VERSION 5.8 ;
BUSBITCHARS "[]" ;
DIVIDERCHAR "/" ;
UNITS
    DATABASE MICRONS 1000 ;
END UNITS

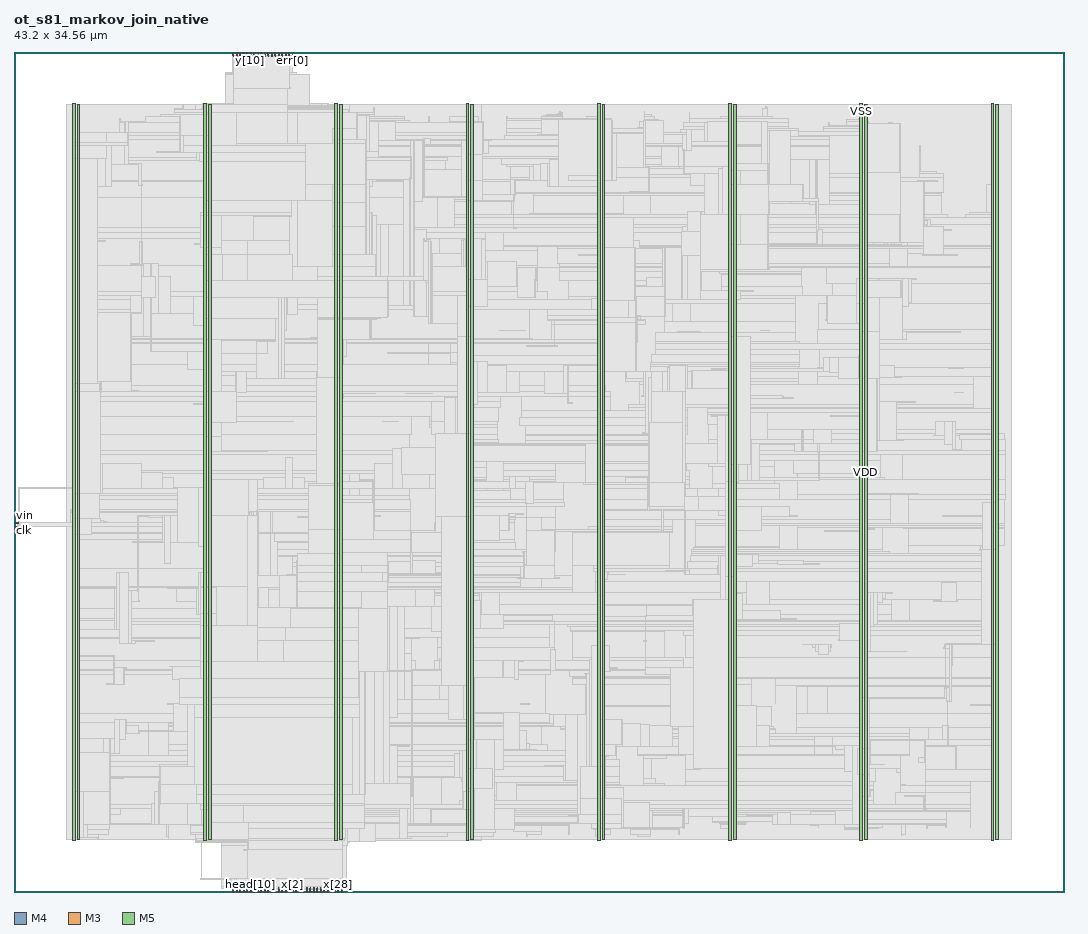
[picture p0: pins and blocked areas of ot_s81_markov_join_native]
MACRO ot_s81_markov_join_native
  FOREIGN ot_s81_markov_join_native 0 0 ;
  CLASS BLOCK ;
  SIZE 43.2 BY 34.56 ;
  PIN clk
    DIRECTION INPUT ;
    USE SIGNAL ;
    PORT
      LAYER M4 ;
        RECT  0 14.88 0.192 14.904 ;
    END
  END clk
  PIN err[0]
    DIRECTION OUTPUT ;
    USE SIGNAL ;
    PORT
      LAYER M3 ;
        RECT  11.448 34.416 11.466 34.56 ;
    END
  END err[0]
  PIN err[1]
    DIRECTION OUTPUT ;
    USE SIGNAL ;
    PORT
      LAYER M5 ;
        RECT  11.328 34.368 11.352 34.56 ;
    END
  END err[1]
  PIN head[0]
    DIRECTION INPUT ;
    USE SIGNAL ;
    PORT
      LAYER M3 ;
        RECT  9 0 9.018 0.144 ;
    END
  END head[0]
  PIN head[10]
    DIRECTION INPUT ;
    USE SIGNAL ;
    PORT
      LAYER M3 ;
        RECT  9.72 0 9.738 0.144 ;
    END
  END head[10]
  PIN head[11]
    DIRECTION INPUT ;
    USE SIGNAL ;
    PORT
      LAYER M5 ;
        RECT  9.744 0 9.768 0.192 ;
    END
  END head[11]
  PIN head[12]
    DIRECTION INPUT ;
    USE SIGNAL ;
    PORT
      LAYER M3 ;
        RECT  9.864 0 9.882 0.144 ;
    END
  END head[12]
  PIN head[13]
    DIRECTION INPUT ;
    USE SIGNAL ;
    PORT
      LAYER M5 ;
        RECT  9.888 0 9.912 0.192 ;
    END
  END head[13]
  PIN head[14]
    DIRECTION INPUT ;
    USE SIGNAL ;
    PORT
      LAYER M3 ;
        RECT  10.008 0 10.026 0.144 ;
    END
  END head[14]
  PIN head[15]
    DIRECTION INPUT ;
    USE SIGNAL ;
    PORT
      LAYER M5 ;
        RECT  10.032 0 10.056 0.192 ;
    END
  END head[15]
  PIN head[16]
    DIRECTION INPUT ;
    USE SIGNAL ;
    PORT
      LAYER M3 ;
        RECT  10.152 0 10.17 0.144 ;
    END
  END head[16]
  PIN head[17]
    DIRECTION INPUT ;
    USE SIGNAL ;
    PORT
      LAYER M5 ;
        RECT  10.176 0 10.2 0.192 ;
    END
  END head[17]
  PIN head[18]
    DIRECTION INPUT ;
    USE SIGNAL ;
    PORT
      LAYER M3 ;
        RECT  10.296 0 10.314 0.144 ;
    END
  END head[18]
  PIN head[19]
    DIRECTION INPUT ;
    USE SIGNAL ;
    PORT
      LAYER M5 ;
        RECT  10.32 0 10.344 0.192 ;
    END
  END head[19]
  PIN head[1]
    DIRECTION INPUT ;
    USE SIGNAL ;
    PORT
      LAYER M5 ;
        RECT  9.024 0 9.048 0.192 ;
    END
  END head[1]
  PIN head[20]
    DIRECTION INPUT ;
    USE SIGNAL ;
    PORT
      LAYER M3 ;
        RECT  10.44 0 10.458 0.144 ;
    END
  END head[20]
  PIN head[21]
    DIRECTION INPUT ;
    USE SIGNAL ;
    PORT
      LAYER M5 ;
        RECT  10.464 0 10.488 0.192 ;
    END
  END head[21]
  PIN head[22]
    DIRECTION INPUT ;
    USE SIGNAL ;
    PORT
      LAYER M3 ;
        RECT  10.584 0 10.602 0.144 ;
    END
  END head[22]
  PIN head[23]
    DIRECTION INPUT ;
    USE SIGNAL ;
    PORT
      LAYER M5 ;
        RECT  10.608 0 10.632 0.192 ;
    END
  END head[23]
  PIN head[24]
    DIRECTION INPUT ;
    USE SIGNAL ;
    PORT
      LAYER M3 ;
        RECT  10.728 0 10.746 0.144 ;
    END
  END head[24]
  PIN head[25]
    DIRECTION INPUT ;
    USE SIGNAL ;
    PORT
      LAYER M5 ;
        RECT  10.752 0 10.776 0.192 ;
    END
  END head[25]
  PIN head[26]
    DIRECTION INPUT ;
    USE SIGNAL ;
    PORT
      LAYER M3 ;
        RECT  10.872 0 10.89 0.144 ;
    END
  END head[26]
  PIN head[27]
    DIRECTION INPUT ;
    USE SIGNAL ;
    PORT
      LAYER M5 ;
        RECT  10.896 0 10.92 0.192 ;
    END
  END head[27]
  PIN head[28]
    DIRECTION INPUT ;
    USE SIGNAL ;
    PORT
      LAYER M3 ;
        RECT  11.016 0 11.034 0.144 ;
    END
  END head[28]
  PIN head[29]
    DIRECTION INPUT ;
    USE SIGNAL ;
    PORT
      LAYER M5 ;
        RECT  11.04 0 11.064 0.192 ;
    END
  END head[29]
  PIN head[2]
    DIRECTION INPUT ;
    USE SIGNAL ;
    PORT
      LAYER M3 ;
        RECT  9.144 0 9.162 0.144 ;
    END
  END head[2]
  PIN head[30]
    DIRECTION INPUT ;
    USE SIGNAL ;
    PORT
      LAYER M3 ;
        RECT  11.16 0 11.178 0.144 ;
    END
  END head[30]
  PIN head[31]
    DIRECTION INPUT ;
    USE SIGNAL ;
    PORT
      LAYER M5 ;
        RECT  11.184 0 11.208 0.192 ;
    END
  END head[31]
  PIN head[3]
    DIRECTION INPUT ;
    USE SIGNAL ;
    PORT
      LAYER M5 ;
        RECT  9.168 0 9.192 0.192 ;
    END
  END head[3]
  PIN head[4]
    DIRECTION INPUT ;
    USE SIGNAL ;
    PORT
      LAYER M3 ;
        RECT  9.288 0 9.306 0.144 ;
    END
  END head[4]
  PIN head[5]
    DIRECTION INPUT ;
    USE SIGNAL ;
    PORT
      LAYER M5 ;
        RECT  9.312 0 9.336 0.192 ;
    END
  END head[5]
  PIN head[6]
    DIRECTION INPUT ;
    USE SIGNAL ;
    PORT
      LAYER M3 ;
        RECT  9.432 0 9.45 0.144 ;
    END
  END head[6]
  PIN head[7]
    DIRECTION INPUT ;
    USE SIGNAL ;
    PORT
      LAYER M5 ;
        RECT  9.456 0 9.48 0.192 ;
    END
  END head[7]
  PIN head[8]
    DIRECTION INPUT ;
    USE SIGNAL ;
    PORT
      LAYER M3 ;
        RECT  9.576 0 9.594 0.144 ;
    END
  END head[8]
  PIN head[9]
    DIRECTION INPUT ;
    USE SIGNAL ;
    PORT
      LAYER M5 ;
        RECT  9.6 0 9.624 0.192 ;
    END
  END head[9]
  PIN rst_n
    DIRECTION INPUT ;
    USE SIGNAL ;
    PORT
      LAYER M4 ;
        RECT  0 15.024 0.192 15.048 ;
    END
  END rst_n
  PIN vin
    DIRECTION INPUT ;
    USE SIGNAL ;
    PORT
      LAYER M4 ;
        RECT  0 15.168 0.192 15.192 ;
    END
  END vin
  PIN vout
    DIRECTION OUTPUT ;
    USE SIGNAL ;
    PORT
      LAYER M3 ;
        RECT  11.304 34.416 11.322 34.56 ;
    END
  END vout
  PIN x[0]
    DIRECTION INPUT ;
    USE SIGNAL ;
    PORT
      LAYER M3 ;
        RECT  11.304 0 11.322 0.144 ;
    END
  END x[0]
  PIN x[10]
    DIRECTION INPUT ;
    USE SIGNAL ;
    PORT
      LAYER M3 ;
        RECT  12.024 0 12.042 0.144 ;
    END
  END x[10]
  PIN x[11]
    DIRECTION INPUT ;
    USE SIGNAL ;
    PORT
      LAYER M5 ;
        RECT  12.048 0 12.072 0.192 ;
    END
  END x[11]
  PIN x[12]
    DIRECTION INPUT ;
    USE SIGNAL ;
    PORT
      LAYER M3 ;
        RECT  12.168 0 12.186 0.144 ;
    END
  END x[12]
  PIN x[13]
    DIRECTION INPUT ;
    USE SIGNAL ;
    PORT
      LAYER M5 ;
        RECT  12.192 0 12.216 0.192 ;
    END
  END x[13]
  PIN x[14]
    DIRECTION INPUT ;
    USE SIGNAL ;
    PORT
      LAYER M3 ;
        RECT  12.312 0 12.33 0.144 ;
    END
  END x[14]
  PIN x[15]
    DIRECTION INPUT ;
    USE SIGNAL ;
    PORT
      LAYER M5 ;
        RECT  12.336 0 12.36 0.192 ;
    END
  END x[15]
  PIN x[16]
    DIRECTION INPUT ;
    USE SIGNAL ;
    PORT
      LAYER M3 ;
        RECT  12.456 0 12.474 0.144 ;
    END
  END x[16]
  PIN x[17]
    DIRECTION INPUT ;
    USE SIGNAL ;
    PORT
      LAYER M5 ;
        RECT  12.48 0 12.504 0.192 ;
    END
  END x[17]
  PIN x[18]
    DIRECTION INPUT ;
    USE SIGNAL ;
    PORT
      LAYER M3 ;
        RECT  12.6 0 12.618 0.144 ;
    END
  END x[18]
  PIN x[19]
    DIRECTION INPUT ;
    USE SIGNAL ;
    PORT
      LAYER M5 ;
        RECT  12.624 0 12.648 0.192 ;
    END
  END x[19]
  PIN x[1]
    DIRECTION INPUT ;
    USE SIGNAL ;
    PORT
      LAYER M5 ;
        RECT  11.328 0 11.352 0.192 ;
    END
  END x[1]
  PIN x[20]
    DIRECTION INPUT ;
    USE SIGNAL ;
    PORT
      LAYER M3 ;
        RECT  12.744 0 12.762 0.144 ;
    END
  END x[20]
  PIN x[21]
    DIRECTION INPUT ;
    USE SIGNAL ;
    PORT
      LAYER M5 ;
        RECT  12.768 0 12.792 0.192 ;
    END
  END x[21]
  PIN x[22]
    DIRECTION INPUT ;
    USE SIGNAL ;
    PORT
      LAYER M3 ;
        RECT  12.888 0 12.906 0.144 ;
    END
  END x[22]
  PIN x[23]
    DIRECTION INPUT ;
    USE SIGNAL ;
    PORT
      LAYER M5 ;
        RECT  12.912 0 12.936 0.192 ;
    END
  END x[23]
  PIN x[24]
    DIRECTION INPUT ;
    USE SIGNAL ;
    PORT
      LAYER M3 ;
        RECT  13.032 0 13.05 0.144 ;
    END
  END x[24]
  PIN x[25]
    DIRECTION INPUT ;
    USE SIGNAL ;
    PORT
      LAYER M5 ;
        RECT  13.056 0 13.08 0.192 ;
    END
  END x[25]
  PIN x[26]
    DIRECTION INPUT ;
    USE SIGNAL ;
    PORT
      LAYER M3 ;
        RECT  13.176 0 13.194 0.144 ;
    END
  END x[26]
  PIN x[27]
    DIRECTION INPUT ;
    USE SIGNAL ;
    PORT
      LAYER M5 ;
        RECT  13.2 0 13.224 0.192 ;
    END
  END x[27]
  PIN x[28]
    DIRECTION INPUT ;
    USE SIGNAL ;
    PORT
      LAYER M3 ;
        RECT  13.32 0 13.338 0.144 ;
    END
  END x[28]
  PIN x[29]
    DIRECTION INPUT ;
    USE SIGNAL ;
    PORT
      LAYER M5 ;
        RECT  13.344 0 13.368 0.192 ;
    END
  END x[29]
  PIN x[2]
    DIRECTION INPUT ;
    USE SIGNAL ;
    PORT
      LAYER M3 ;
        RECT  11.448 0 11.466 0.144 ;
    END
  END x[2]
  PIN x[30]
    DIRECTION INPUT ;
    USE SIGNAL ;
    PORT
      LAYER M3 ;
        RECT  13.464 0 13.482 0.144 ;
    END
  END x[30]
  PIN x[31]
    DIRECTION INPUT ;
    USE SIGNAL ;
    PORT
      LAYER M5 ;
        RECT  13.488 0 13.512 0.192 ;
    END
  END x[31]
  PIN x[3]
    DIRECTION INPUT ;
    USE SIGNAL ;
    PORT
      LAYER M5 ;
        RECT  11.472 0 11.496 0.192 ;
    END
  END x[3]
  PIN x[4]
    DIRECTION INPUT ;
    USE SIGNAL ;
    PORT
      LAYER M3 ;
        RECT  11.592 0 11.61 0.144 ;
    END
  END x[4]
  PIN x[5]
    DIRECTION INPUT ;
    USE SIGNAL ;
    PORT
      LAYER M5 ;
        RECT  11.616 0 11.64 0.192 ;
    END
  END x[5]
  PIN x[6]
    DIRECTION INPUT ;
    USE SIGNAL ;
    PORT
      LAYER M3 ;
        RECT  11.736 0 11.754 0.144 ;
    END
  END x[6]
  PIN x[7]
    DIRECTION INPUT ;
    USE SIGNAL ;
    PORT
      LAYER M5 ;
        RECT  11.76 0 11.784 0.192 ;
    END
  END x[7]
  PIN x[8]
    DIRECTION INPUT ;
    USE SIGNAL ;
    PORT
      LAYER M3 ;
        RECT  11.88 0 11.898 0.144 ;
    END
  END x[8]
  PIN x[9]
    DIRECTION INPUT ;
    USE SIGNAL ;
    PORT
      LAYER M5 ;
        RECT  11.904 0 11.928 0.192 ;
    END
  END x[9]
  PIN y[0]
    DIRECTION OUTPUT ;
    USE SIGNAL ;
    PORT
      LAYER M3 ;
        RECT  9 34.416 9.018 34.56 ;
    END
  END y[0]
  PIN y[10]
    DIRECTION OUTPUT ;
    USE SIGNAL ;
    PORT
      LAYER M3 ;
        RECT  9.72 34.416 9.738 34.56 ;
    END
  END y[10]
  PIN y[11]
    DIRECTION OUTPUT ;
    USE SIGNAL ;
    PORT
      LAYER M5 ;
        RECT  9.744 34.368 9.768 34.56 ;
    END
  END y[11]
  PIN y[12]
    DIRECTION OUTPUT ;
    USE SIGNAL ;
    PORT
      LAYER M3 ;
        RECT  9.864 34.416 9.882 34.56 ;
    END
  END y[12]
  PIN y[13]
    DIRECTION OUTPUT ;
    USE SIGNAL ;
    PORT
      LAYER M5 ;
        RECT  9.888 34.368 9.912 34.56 ;
    END
  END y[13]
  PIN y[14]
    DIRECTION OUTPUT ;
    USE SIGNAL ;
    PORT
      LAYER M3 ;
        RECT  10.008 34.416 10.026 34.56 ;
    END
  END y[14]
  PIN y[15]
    DIRECTION OUTPUT ;
    USE SIGNAL ;
    PORT
      LAYER M5 ;
        RECT  10.032 34.368 10.056 34.56 ;
    END
  END y[15]
  PIN y[16]
    DIRECTION OUTPUT ;
    USE SIGNAL ;
    PORT
      LAYER M3 ;
        RECT  10.152 34.416 10.17 34.56 ;
    END
  END y[16]
  PIN y[17]
    DIRECTION OUTPUT ;
    USE SIGNAL ;
    PORT
      LAYER M5 ;
        RECT  10.176 34.368 10.2 34.56 ;
    END
  END y[17]
  PIN y[18]
    DIRECTION OUTPUT ;
    USE SIGNAL ;
    PORT
      LAYER M3 ;
        RECT  10.296 34.416 10.314 34.56 ;
    END
  END y[18]
  PIN y[19]
    DIRECTION OUTPUT ;
    USE SIGNAL ;
    PORT
      LAYER M5 ;
        RECT  10.32 34.368 10.344 34.56 ;
    END
  END y[19]
  PIN y[1]
    DIRECTION OUTPUT ;
    USE SIGNAL ;
    PORT
      LAYER M5 ;
        RECT  9.024 34.368 9.048 34.56 ;
    END
  END y[1]
  PIN y[20]
    DIRECTION OUTPUT ;
    USE SIGNAL ;
    PORT
      LAYER M3 ;
        RECT  10.44 34.416 10.458 34.56 ;
    END
  END y[20]
  PIN y[21]
    DIRECTION OUTPUT ;
    USE SIGNAL ;
    PORT
      LAYER M5 ;
        RECT  10.464 34.368 10.488 34.56 ;
    END
  END y[21]
  PIN y[22]
    DIRECTION OUTPUT ;
    USE SIGNAL ;
    PORT
      LAYER M3 ;
        RECT  10.584 34.416 10.602 34.56 ;
    END
  END y[22]
  PIN y[23]
    DIRECTION OUTPUT ;
    USE SIGNAL ;
    PORT
      LAYER M5 ;
        RECT  10.608 34.368 10.632 34.56 ;
    END
  END y[23]
  PIN y[24]
    DIRECTION OUTPUT ;
    USE SIGNAL ;
    PORT
      LAYER M3 ;
        RECT  10.728 34.416 10.746 34.56 ;
    END
  END y[24]
  PIN y[25]
    DIRECTION OUTPUT ;
    USE SIGNAL ;
    PORT
      LAYER M5 ;
        RECT  10.752 34.368 10.776 34.56 ;
    END
  END y[25]
  PIN y[26]
    DIRECTION OUTPUT ;
    USE SIGNAL ;
    PORT
      LAYER M3 ;
        RECT  10.872 34.416 10.89 34.56 ;
    END
  END y[26]
  PIN y[27]
    DIRECTION OUTPUT ;
    USE SIGNAL ;
    PORT
      LAYER M5 ;
        RECT  10.896 34.368 10.92 34.56 ;
    END
  END y[27]
  PIN y[28]
    DIRECTION OUTPUT ;
    USE SIGNAL ;
    PORT
      LAYER M3 ;
        RECT  11.016 34.416 11.034 34.56 ;
    END
  END y[28]
  PIN y[29]
    DIRECTION OUTPUT ;
    USE SIGNAL ;
    PORT
      LAYER M5 ;
        RECT  11.04 34.368 11.064 34.56 ;
    END
  END y[29]
  PIN y[2]
    DIRECTION OUTPUT ;
    USE SIGNAL ;
    PORT
      LAYER M3 ;
        RECT  9.144 34.416 9.162 34.56 ;
    END
  END y[2]
  PIN y[30]
    DIRECTION OUTPUT ;
    USE SIGNAL ;
    PORT
      LAYER M3 ;
        RECT  11.16 34.416 11.178 34.56 ;
    END
  END y[30]
  PIN y[31]
    DIRECTION OUTPUT ;
    USE SIGNAL ;
    PORT
      LAYER M5 ;
        RECT  11.184 34.368 11.208 34.56 ;
    END
  END y[31]
  PIN y[3]
    DIRECTION OUTPUT ;
    USE SIGNAL ;
    PORT
      LAYER M5 ;
        RECT  9.168 34.368 9.192 34.56 ;
    END
  END y[3]
  PIN y[4]
    DIRECTION OUTPUT ;
    USE SIGNAL ;
    PORT
      LAYER M3 ;
        RECT  9.288 34.416 9.306 34.56 ;
    END
  END y[4]
  PIN y[5]
    DIRECTION OUTPUT ;
    USE SIGNAL ;
    PORT
      LAYER M5 ;
        RECT  9.312 34.368 9.336 34.56 ;
    END
  END y[5]
  PIN y[6]
    DIRECTION OUTPUT ;
    USE SIGNAL ;
    PORT
      LAYER M3 ;
        RECT  9.432 34.416 9.45 34.56 ;
    END
  END y[6]
  PIN y[7]
    DIRECTION OUTPUT ;
    USE SIGNAL ;
    PORT
      LAYER M5 ;
        RECT  9.456 34.368 9.48 34.56 ;
    END
  END y[7]
  PIN y[8]
    DIRECTION OUTPUT ;
    USE SIGNAL ;
    PORT
      LAYER M3 ;
        RECT  9.576 34.416 9.594 34.56 ;
    END
  END y[8]
  PIN y[9]
    DIRECTION OUTPUT ;
    USE SIGNAL ;
    PORT
      LAYER M5 ;
        RECT  9.6 34.368 9.624 34.56 ;
    END
  END y[9]
  PIN VDD
    DIRECTION INOUT ;
    USE POWER ;
    PORT
      LAYER M5 ;
        RECT  40.392 2.151 40.512 32.409 ;
        RECT  34.992 2.151 35.112 32.409 ;
        RECT  29.592 2.151 29.712 32.409 ;
        RECT  24.192 2.151 24.312 32.409 ;
        RECT  18.792 2.151 18.912 32.409 ;
        RECT  13.392 2.151 13.512 32.409 ;
        RECT  7.992 2.151 8.112 32.409 ;
        RECT  2.592 2.151 2.712 32.409 ;
    END
  END VDD
  PIN VSS
    DIRECTION INOUT ;
    USE GROUND ;
    PORT
      LAYER M5 ;
        RECT  40.2 2.137 40.32 32.423 ;
        RECT  34.8 2.137 34.92 32.423 ;
        RECT  29.4 2.137 29.52 32.423 ;
        RECT  24 2.137 24.12 32.423 ;
        RECT  18.6 2.137 18.72 32.423 ;
        RECT  13.2 2.137 13.32 32.423 ;
        RECT  7.8 2.137 7.92 32.423 ;
        RECT  2.4 2.137 2.52 32.423 ;
    END
  END VSS
  # OT_OBS_CLOSED layer=M5 d_um=1.536 added=83
  OBS
    LAYER RVTN ;
     RECT  2.16 2.16 41.04 2.295 ;
     RECT  2.16 2.565 41.04 2.835 ;
     RECT  2.16 3.105 41.04 3.375 ;
     RECT  2.16 3.645 41.04 3.915 ;
     RECT  2.16 4.185 41.04 4.455 ;
     RECT  2.16 4.725 41.04 4.995 ;
     RECT  2.16 5.265 41.04 5.535 ;
     RECT  2.16 5.805 41.04 6.075 ;
     RECT  2.16 6.345 41.04 6.615 ;
     RECT  2.16 6.885 41.04 7.155 ;
     RECT  2.16 7.425 41.04 7.695 ;
     RECT  2.16 7.965 41.04 8.235 ;
     RECT  2.16 8.505 41.04 8.775 ;
     RECT  2.16 9.045 41.04 9.315 ;
     RECT  2.16 9.585 41.04 9.855 ;
     RECT  2.16 10.125 41.04 10.395 ;
     RECT  2.16 10.665 41.04 10.935 ;
     RECT  2.16 11.205 41.04 11.475 ;
     RECT  2.16 11.745 41.04 12.015 ;
     RECT  2.16 12.285 41.04 12.555 ;
     RECT  2.16 12.825 41.04 13.095 ;
     RECT  2.16 13.365 41.04 13.635 ;
     RECT  2.16 13.905 41.04 14.175 ;
     RECT  2.16 14.445 41.04 14.715 ;
     RECT  2.16 14.985 41.04 15.255 ;
     RECT  2.16 15.525 41.04 15.795 ;
     RECT  2.16 16.065 41.04 16.335 ;
     RECT  2.16 16.605 41.04 16.875 ;
     RECT  2.16 17.145 41.04 17.415 ;
     RECT  2.16 17.685 41.04 17.955 ;
     RECT  2.16 18.225 41.04 18.495 ;
     RECT  2.16 18.765 41.04 19.035 ;
     RECT  2.16 19.305 41.04 19.575 ;
     RECT  2.16 19.845 41.04 20.115 ;
     RECT  2.16 20.385 41.04 20.655 ;
     RECT  2.16 20.925 41.04 21.195 ;
     RECT  2.16 21.465 41.04 21.735 ;
     RECT  2.16 22.005 41.04 22.275 ;
     RECT  2.16 22.545 41.04 22.815 ;
     RECT  2.16 23.085 41.04 23.355 ;
     RECT  2.16 23.625 41.04 23.895 ;
     RECT  2.16 24.165 41.04 24.435 ;
     RECT  2.16 24.705 41.04 24.975 ;
     RECT  2.16 25.245 41.04 25.515 ;
     RECT  2.16 25.785 41.04 26.055 ;
     RECT  2.16 26.325 41.04 26.595 ;
     RECT  2.16 26.865 41.04 27.135 ;
     RECT  2.16 27.405 41.04 27.675 ;
     RECT  2.16 27.945 41.04 28.215 ;
     RECT  2.16 28.485 41.04 28.755 ;
     RECT  2.16 29.025 41.04 29.295 ;
     RECT  2.16 29.565 41.04 29.835 ;
     RECT  2.16 30.105 41.04 30.375 ;
     RECT  2.16 30.645 41.04 30.915 ;
     RECT  2.16 31.185 41.04 31.455 ;
     RECT  2.16 31.725 41.04 31.995 ;
     RECT  2.16 32.265 41.04 32.4 ;
    LAYER RVTP ;
     RECT  2.16 2.295 41.04 2.565 ;
     RECT  2.16 2.835 41.04 3.105 ;
     RECT  2.16 3.375 41.04 3.645 ;
     RECT  2.16 3.915 41.04 4.185 ;
     RECT  2.16 4.455 41.04 4.725 ;
     RECT  2.16 4.995 41.04 5.265 ;
     RECT  2.16 5.535 41.04 5.805 ;
     RECT  2.16 6.075 41.04 6.345 ;
     RECT  2.16 6.615 41.04 6.885 ;
     RECT  2.16 7.155 41.04 7.425 ;
     RECT  2.16 7.695 41.04 7.965 ;
     RECT  2.16 8.235 41.04 8.505 ;
     RECT  2.16 8.775 41.04 9.045 ;
     RECT  2.16 9.315 41.04 9.585 ;
     RECT  2.16 9.855 41.04 10.125 ;
     RECT  2.16 10.395 41.04 10.665 ;
     RECT  2.16 10.935 41.04 11.205 ;
     RECT  2.16 11.475 41.04 11.745 ;
     RECT  2.16 12.015 41.04 12.285 ;
     RECT  2.16 12.555 41.04 12.825 ;
     RECT  2.16 13.095 41.04 13.365 ;
     RECT  2.16 13.635 41.04 13.905 ;
     RECT  2.16 14.175 41.04 14.445 ;
     RECT  2.16 14.715 41.04 14.985 ;
     RECT  2.16 15.255 41.04 15.525 ;
     RECT  2.16 15.795 41.04 16.065 ;
     RECT  2.16 16.335 41.04 16.605 ;
     RECT  2.16 16.875 41.04 17.145 ;
     RECT  2.16 17.415 41.04 17.685 ;
     RECT  2.16 17.955 41.04 18.225 ;
     RECT  2.16 18.495 41.04 18.765 ;
     RECT  2.16 19.035 41.04 19.305 ;
     RECT  2.16 19.575 41.04 19.845 ;
     RECT  2.16 20.115 41.04 20.385 ;
     RECT  2.16 20.655 41.04 20.925 ;
     RECT  2.16 21.195 41.04 21.465 ;
     RECT  2.16 21.735 41.04 22.005 ;
     RECT  2.16 22.275 41.04 22.545 ;
     RECT  2.16 22.815 41.04 23.085 ;
     RECT  2.16 23.355 41.04 23.625 ;
     RECT  2.16 23.895 41.04 24.165 ;
     RECT  2.16 24.435 41.04 24.705 ;
     RECT  2.16 24.975 41.04 25.245 ;
     RECT  2.16 25.515 41.04 25.785 ;
     RECT  2.16 26.055 41.04 26.325 ;
     RECT  2.16 26.595 41.04 26.865 ;
     RECT  2.16 27.135 41.04 27.405 ;
     RECT  2.16 27.675 41.04 27.945 ;
     RECT  2.16 28.215 41.04 28.485 ;
     RECT  2.16 28.755 41.04 29.025 ;
     RECT  2.16 29.295 41.04 29.565 ;
     RECT  2.16 29.835 41.04 30.105 ;
     RECT  2.16 30.375 41.04 30.645 ;
     RECT  2.16 30.915 41.04 31.185 ;
     RECT  2.16 31.455 41.04 31.725 ;
     RECT  2.16 31.995 41.04 32.265 ;
    LAYER M1 ;
     RECT  2.16 2.151 41.04 32.409 ;
    LAYER M2 ;
     RECT  2.16 2.151 7.483 32.409 ;
     RECT  7.483 2.034 7.771 32.409 ;
     RECT  7.771 2.034 8.699 32.454 ;
     RECT  8.699 2.151 9.023 32.454 ;
     RECT  9.023 2.151 9.679 32.409 ;
     RECT  9.679 2.106 9.787 32.409 ;
     RECT  9.787 2.106 9.859 32.994 ;
     RECT  9.859 2.106 10.067 33.759 ;
     RECT  8.527 0.144 10.319 0.162 ;
     RECT  10.067 2.106 10.571 33.066 ;
     RECT  10.571 2.106 10.859 32.409 ;
     RECT  11.155 33.696 11.299 33.714 ;
     RECT  10.859 2.151 11.587 32.409 ;
     RECT  11.299 33.624 11.615 33.714 ;
     RECT  11.587 2.151 11.903 32.526 ;
     RECT  11.615 33.624 12.155 33.642 ;
     RECT  11.903 2.151 12.667 32.454 ;
     RECT  12.667 1.728 12.911 32.454 ;
     RECT  12.911 2.034 12.947 32.454 ;
     RECT  12.415 0.144 13.459 0.162 ;
     RECT  13.459 0.144 13.631 0.234 ;
     RECT  13.631 0.216 13.667 0.234 ;
     RECT  12.947 2.034 13.811 32.409 ;
     RECT  13.811 2.106 19.247 32.409 ;
     RECT  19.247 2.151 41.04 32.409 ;
    LAYER M3 ;
     RECT  9 0.108 13.482 0.139 ;
     RECT  8.532 0.139 13.626 0.211 ;
     RECT  8.532 0.211 13.662 1.915 ;
     RECT  7.704 0.523 7.722 2.029 ;
     RECT  8.532 1.915 13.698 2.029 ;
     RECT  7.488 2.029 7.722 2.065 ;
     RECT  8.532 2.029 13.806 2.065 ;
     RECT  7.488 2.065 13.806 2.107 ;
     RECT  14.832 2.059 14.85 2.107 ;
     RECT  19.224 2.101 19.242 2.143 ;
     RECT  7.488 2.107 14.85 2.191 ;
     RECT  2.415 2.143 2.505 2.251 ;
     RECT  3.456 2.191 3.474 2.251 ;
     RECT  6.336 2.191 6.354 2.263 ;
     RECT  16.164 2.191 16.362 2.263 ;
     RECT  16.164 2.263 17.586 2.299 ;
     RECT  18.615 2.143 19.242 2.299 ;
     RECT  24.015 2.143 24.105 2.299 ;
     RECT  26.172 2.263 26.19 2.299 ;
     RECT  2.415 2.251 3.474 2.371 ;
     RECT  7.452 2.191 14.85 2.371 ;
     RECT  21.096 2.263 21.114 2.371 ;
     RECT  23.94 2.299 24.105 2.371 ;
     RECT  25.668 2.299 26.19 2.371 ;
     RECT  36.504 2.335 36.522 2.371 ;
     RECT  29.415 2.143 29.505 2.413 ;
     RECT  34.815 2.143 34.905 2.413 ;
     RECT  40.215 2.143 40.305 2.413 ;
     RECT  7.272 2.371 15.426 2.461 ;
     RECT  16.164 2.299 17.838 2.461 ;
     RECT  18.615 2.299 19.746 2.461 ;
     RECT  21.096 2.371 21.69 2.497 ;
     RECT  2.415 2.371 3.87 2.569 ;
     RECT  23.94 2.371 24.534 2.569 ;
     RECT  25.344 2.371 26.19 2.569 ;
     RECT  27.36 2.371 27.378 2.569 ;
     RECT  34.815 2.413 35.097 2.569 ;
     RECT  23.832 2.569 24.534 2.605 ;
     RECT  25.344 2.569 27.378 2.605 ;
     RECT  29.415 2.413 29.697 2.605 ;
     RECT  34.164 2.569 35.097 2.605 ;
     RECT  34.164 2.605 35.586 2.641 ;
     RECT  7.272 2.461 19.818 2.731 ;
     RECT  20.556 2.497 21.69 2.731 ;
     RECT  22.824 2.371 22.842 2.731 ;
     RECT  33.084 2.641 33.102 2.731 ;
     RECT  37.548 2.605 37.566 2.731 ;
     RECT  38.34 2.641 38.358 2.731 ;
     RECT  6.264 2.263 6.354 2.767 ;
     RECT  7.272 2.731 22.842 2.767 ;
     RECT  29.052 2.605 29.697 2.767 ;
     RECT  34.164 2.641 35.73 2.767 ;
     RECT  36.504 2.371 36.666 2.767 ;
     RECT  37.548 2.731 38.358 2.767 ;
     RECT  31.464 2.767 31.482 2.779 ;
     RECT  5.796 2.767 22.842 2.803 ;
     RECT  23.76 2.605 27.378 2.803 ;
     RECT  29.052 2.767 30.114 2.803 ;
     RECT  33.876 2.767 35.73 2.803 ;
     RECT  36.504 2.767 38.358 2.803 ;
     RECT  5.796 2.803 27.738 2.839 ;
     RECT  29.016 2.803 30.114 2.875 ;
     RECT  28.728 2.875 30.186 2.911 ;
     RECT  31.212 2.779 31.482 2.911 ;
     RECT  32.76 2.731 33.102 3.001 ;
     RECT  33.876 2.803 38.358 3.001 ;
     RECT  5.652 2.839 27.738 3.109 ;
     RECT  28.728 2.911 31.77 3.109 ;
     RECT  2.415 2.569 3.942 3.181 ;
     RECT  5.652 3.109 31.77 3.181 ;
     RECT  5.652 3.181 31.842 3.259 ;
     RECT  32.76 3.001 38.358 3.307 ;
     RECT  39.348 2.641 39.366 3.307 ;
     RECT  5.652 3.259 31.95 3.343 ;
     RECT  32.76 3.307 39.366 3.343 ;
     RECT  2.415 3.181 4.374 3.415 ;
     RECT  5.652 3.343 39.366 3.415 ;
     RECT  2.415 3.415 39.366 3.605 ;
     RECT  18.324 3.605 35.37 3.749 ;
     RECT  18.504 3.749 19.854 3.983 ;
     RECT  36.288 3.605 39.366 4.109 ;
     RECT  20.664 3.749 35.37 4.379 ;
     RECT  36.468 4.109 39.366 4.379 ;
     RECT  20.664 4.379 24.966 4.415 ;
     RECT  36.468 4.379 36.666 4.415 ;
     RECT  25.884 4.379 26.766 4.451 ;
     RECT  19.692 3.983 19.854 4.495 ;
     RECT  20.664 4.415 24.93 4.495 ;
     RECT  18.504 3.983 18.954 4.531 ;
     RECT  27.648 4.379 35.37 4.531 ;
     RECT  37.512 4.379 39.366 4.531 ;
     RECT  40.215 2.413 40.497 4.531 ;
     RECT  25.884 4.451 26.406 4.685 ;
     RECT  2.415 3.605 17.586 4.699 ;
     RECT  18.432 4.531 18.954 4.699 ;
     RECT  2.415 4.699 18.954 4.765 ;
     RECT  19.692 4.495 24.93 4.765 ;
     RECT  36.468 4.415 36.486 4.927 ;
     RECT  27.648 4.531 35.442 5.071 ;
     RECT  36.324 4.927 36.486 5.071 ;
     RECT  2.415 4.765 24.93 5.165 ;
     RECT  37.512 4.531 40.497 5.341 ;
     RECT  2.415 5.165 22.77 5.369 ;
     RECT  23.508 5.165 24.93 5.459 ;
     RECT  25.884 4.685 26.226 5.503 ;
     RECT  37.224 5.341 40.497 5.531 ;
     RECT  2.415 5.369 22.734 5.603 ;
     RECT  25.884 5.503 26.838 5.611 ;
     RECT  27.648 5.071 36.486 5.611 ;
     RECT  25.668 5.611 36.846 5.639 ;
     RECT  6.372 5.603 22.734 5.837 ;
     RECT  6.372 5.837 21.942 6.071 ;
     RECT  23.508 5.459 24.786 6.277 ;
     RECT  25.668 5.639 32.922 6.277 ;
     RECT  37.656 5.531 40.497 6.277 ;
     RECT  23.508 6.277 32.922 6.385 ;
     RECT  33.696 5.639 36.846 6.385 ;
     RECT  23.508 6.385 36.846 6.539 ;
     RECT  22.716 5.837 22.734 6.691 ;
     RECT  23.508 6.539 31.338 6.691 ;
     RECT  22.5 6.691 31.338 6.719 ;
     RECT  32.184 6.539 36.846 6.781 ;
     RECT  37.62 6.277 40.497 6.781 ;
     RECT  22.5 6.719 31.266 6.809 ;
     RECT  6.372 6.071 21.69 6.811 ;
     RECT  22.5 6.809 22.734 6.811 ;
     RECT  6.372 6.811 22.734 6.845 ;
     RECT  6.372 6.845 22.23 6.953 ;
     RECT  2.415 5.603 5.526 6.961 ;
     RECT  6.372 6.953 22.05 6.961 ;
     RECT  2.415 6.961 22.05 7.325 ;
     RECT  32.184 6.781 40.497 7.349 ;
     RECT  23.508 6.809 31.158 7.619 ;
     RECT  23.508 7.619 30.546 7.661 ;
     RECT  32.184 7.349 32.634 8.473 ;
     RECT  33.48 7.349 40.497 8.473 ;
     RECT  31.32 7.771 31.338 8.509 ;
     RECT  32.184 8.473 40.497 8.509 ;
     RECT  23.508 7.661 30.33 8.545 ;
     RECT  22.968 8.545 30.33 8.779 ;
     RECT  31.32 8.509 40.497 8.779 ;
     RECT  22.968 8.779 40.497 8.807 ;
     RECT  22.968 8.807 27.558 8.851 ;
     RECT  2.415 7.325 21.87 8.941 ;
     RECT  2.415 8.941 22.086 9.115 ;
     RECT  22.86 8.851 27.558 9.115 ;
     RECT  2.415 9.115 27.558 9.149 ;
     RECT  2.415 9.149 16.506 9.509 ;
     RECT  17.28 9.149 27.558 9.509 ;
     RECT  17.28 9.509 22.23 9.545 ;
     RECT  22.968 9.509 27.558 9.653 ;
     RECT  28.296 8.807 40.497 9.661 ;
     RECT  17.424 9.545 22.23 10.049 ;
     RECT  2.415 9.509 16.362 10.435 ;
     RECT  2.415 10.435 16.686 10.471 ;
     RECT  17.424 10.049 22.05 10.471 ;
     RECT  27.612 9.661 40.497 10.561 ;
     RECT  22.968 9.653 26.766 10.705 ;
     RECT  22.896 10.705 26.766 10.741 ;
     RECT  27.54 10.561 40.497 10.741 ;
     RECT  22.896 10.741 40.497 10.903 ;
     RECT  2.415 10.471 22.05 11.011 ;
     RECT  22.788 10.903 40.497 11.011 ;
     RECT  2.415 11.011 40.497 11.129 ;
     RECT  19.944 11.129 40.497 11.165 ;
     RECT  2.415 11.129 19.17 11.273 ;
     RECT  19.944 11.165 36.09 11.399 ;
     RECT  2.415 11.273 17.73 11.669 ;
     RECT  10.476 11.669 17.73 11.705 ;
     RECT  19.98 11.399 36.09 11.813 ;
     RECT  31.104 11.813 36.09 12.019 ;
     RECT  36.828 11.165 40.497 12.019 ;
     RECT  17.316 11.705 17.73 12.217 ;
     RECT  18.612 11.273 19.17 12.217 ;
     RECT  17.316 12.217 17.802 12.289 ;
     RECT  18.576 12.217 19.17 12.289 ;
     RECT  19.98 11.813 30.15 12.317 ;
     RECT  17.316 12.289 19.17 12.325 ;
     RECT  19.98 12.317 22.986 12.325 ;
     RECT  10.476 11.705 16.506 12.451 ;
     RECT  17.316 12.325 22.986 12.451 ;
     RECT  10.476 12.451 22.986 12.515 ;
     RECT  2.415 11.669 9.666 12.523 ;
     RECT  10.476 12.515 20.826 12.523 ;
     RECT  2.415 12.523 20.826 12.557 ;
     RECT  10.368 12.557 20.826 12.749 ;
     RECT  23.94 12.317 30.15 12.757 ;
     RECT  31.104 12.019 40.497 12.757 ;
     RECT  10.44 12.749 20.826 12.929 ;
     RECT  11.088 12.929 20.826 13.019 ;
     RECT  21.708 12.515 22.986 13.019 ;
     RECT  11.196 13.019 20.826 13.055 ;
     RECT  23.94 12.757 40.497 13.171 ;
     RECT  2.415 12.557 9.27 13.325 ;
     RECT  23.832 13.171 40.497 13.325 ;
     RECT  11.448 13.055 20.826 13.405 ;
     RECT  21.708 13.019 22.23 13.405 ;
     RECT  22.968 13.019 22.986 13.441 ;
     RECT  23.832 13.325 26.982 13.441 ;
     RECT  11.448 13.405 22.23 13.559 ;
     RECT  27.72 13.325 40.497 13.595 ;
     RECT  11.448 13.559 22.194 13.801 ;
     RECT  10.836 13.801 22.194 13.829 ;
     RECT  27.828 13.595 40.497 13.865 ;
     RECT  27.864 13.865 40.497 13.937 ;
     RECT  27.864 13.937 36.018 14.009 ;
     RECT  10.836 13.829 22.158 14.099 ;
     RECT  27.864 14.009 35.73 14.099 ;
     RECT  27.936 14.099 31.482 14.171 ;
     RECT  28.008 14.171 31.482 14.207 ;
     RECT  36.792 13.937 40.497 14.251 ;
     RECT  10.836 14.099 20.646 14.369 ;
     RECT  10.836 14.369 16.326 14.413 ;
     RECT  17.1 14.369 20.61 14.513 ;
     RECT  2.415 13.325 9.054 14.521 ;
     RECT  9.936 14.251 9.954 14.521 ;
     RECT  2.415 14.521 9.954 14.755 ;
     RECT  10.728 14.413 16.326 14.755 ;
     RECT  2.415 14.755 16.326 14.783 ;
     RECT  22.968 13.441 26.982 14.791 ;
     RECT  21.708 14.099 21.978 14.827 ;
     RECT  22.968 14.791 27.09 14.827 ;
     RECT  21.708 14.827 27.09 14.909 ;
     RECT  36.792 14.251 40.734 14.953 ;
     RECT  32.22 14.099 35.73 14.989 ;
     RECT  36.612 14.953 40.734 14.989 ;
     RECT  2.415 14.783 9.378 15.019 ;
     RECT  2.304 15.019 9.378 15.025 ;
     RECT  23.616 14.909 27.09 15.053 ;
     RECT  28.044 14.207 31.482 15.061 ;
     RECT  32.22 14.989 40.734 15.061 ;
     RECT  28.044 15.061 40.734 15.179 ;
     RECT  2.268 15.025 9.378 15.197 ;
     RECT  17.28 14.513 20.61 15.215 ;
     RECT  17.46 15.215 20.61 15.331 ;
     RECT  24.015 15.053 27.09 15.331 ;
     RECT  28.044 15.179 36.054 15.331 ;
     RECT  17.46 15.331 20.646 15.421 ;
     RECT  21.708 14.909 22.266 15.421 ;
     RECT  2.304 15.197 9.378 15.601 ;
     RECT  2.304 15.601 9.774 15.643 ;
     RECT  10.62 14.783 16.326 15.643 ;
     RECT  2.304 15.643 16.326 15.755 ;
     RECT  17.46 15.421 22.266 15.871 ;
     RECT  17.46 15.871 22.662 16.025 ;
     RECT  2.412 15.755 16.326 16.133 ;
     RECT  36.792 15.179 40.734 16.141 ;
     RECT  17.46 16.025 22.59 16.169 ;
     RECT  24.015 15.331 36.054 16.169 ;
     RECT  2.412 16.133 16.29 16.331 ;
     RECT  32.256 16.169 36.054 16.363 ;
     RECT  36.792 16.141 40.806 16.363 ;
     RECT  2.412 16.331 13.497 16.403 ;
     RECT  17.46 16.169 20.43 16.529 ;
     RECT  17.46 16.529 19.422 16.537 ;
     RECT  24.015 16.169 31.482 16.589 ;
     RECT  17.424 16.537 19.422 16.603 ;
     RECT  24.015 16.589 27.81 16.771 ;
     RECT  28.728 16.589 31.482 16.799 ;
     RECT  14.22 16.331 16.29 16.915 ;
     RECT  17.1 16.603 19.422 16.915 ;
     RECT  20.16 16.529 20.43 16.951 ;
     RECT  21.204 16.169 22.59 16.951 ;
     RECT  23.436 16.771 27.81 16.951 ;
     RECT  14.22 16.915 19.422 16.973 ;
     RECT  32.256 16.363 40.806 16.979 ;
     RECT  17.64 16.973 19.422 17.069 ;
     RECT  32.256 16.979 35.802 17.069 ;
     RECT  20.16 16.951 20.466 17.083 ;
     RECT  21.204 16.951 27.81 17.083 ;
     RECT  2.415 16.403 13.497 17.221 ;
     RECT  14.22 16.973 16.398 17.221 ;
     RECT  32.256 17.069 35.658 17.221 ;
     RECT  2.415 17.221 16.398 17.339 ;
     RECT  20.16 17.083 27.81 17.339 ;
     RECT  2.415 17.339 16.326 17.357 ;
     RECT  17.712 17.069 19.422 17.447 ;
     RECT  28.728 16.799 31.302 17.491 ;
     RECT  20.16 17.339 27.666 17.645 ;
     RECT  17.928 17.447 19.422 17.725 ;
     RECT  20.16 17.645 27.018 17.725 ;
     RECT  28.584 17.491 31.302 17.761 ;
     RECT  32.076 17.221 35.658 17.761 ;
     RECT  17.1 17.803 17.118 17.879 ;
     RECT  2.415 17.357 16.29 17.995 ;
     RECT  28.584 17.761 35.658 17.995 ;
     RECT  36.54 16.979 40.806 17.995 ;
     RECT  2.412 17.995 16.29 18.149 ;
     RECT  28.584 17.995 40.806 18.173 ;
     RECT  17.928 17.725 27.018 18.379 ;
     RECT  17.928 18.379 27.054 18.391 ;
     RECT  17.928 18.391 27.198 18.455 ;
     RECT  17.928 18.455 19.926 18.499 ;
     RECT  21.06 18.455 27.198 18.571 ;
     RECT  17.676 18.499 19.926 18.599 ;
     RECT  33.624 18.173 40.806 18.599 ;
     RECT  28.584 18.173 32.886 18.605 ;
     RECT  21.06 18.571 27.27 18.769 ;
     RECT  21.06 18.769 27.45 18.805 ;
     RECT  17.676 18.599 19.89 18.811 ;
     RECT  2.415 18.149 16.29 18.841 ;
     RECT  33.624 18.599 40.734 18.869 ;
     RECT  30.996 18.605 32.886 19.039 ;
     RECT  33.624 18.869 40.497 19.039 ;
     RECT  17.172 18.811 19.89 19.111 ;
     RECT  21.06 18.805 27.702 19.201 ;
     RECT  17.1 19.111 19.89 19.229 ;
     RECT  28.584 18.605 30.186 19.237 ;
     RECT  18.036 19.229 19.89 19.345 ;
     RECT  20.808 19.201 27.702 19.535 ;
     RECT  2.415 18.841 16.362 19.579 ;
     RECT  17.1 19.229 17.19 19.579 ;
     RECT  28.512 19.237 30.186 19.651 ;
     RECT  28.512 19.651 30.222 19.741 ;
     RECT  30.996 19.039 40.497 19.741 ;
     RECT  20.88 19.535 27.702 19.805 ;
     RECT  28.512 19.741 40.497 19.877 ;
     RECT  18.036 19.345 19.926 19.921 ;
     RECT  25.272 19.805 27.702 19.921 ;
     RECT  28.512 19.877 39.474 19.921 ;
     RECT  25.272 19.921 39.474 20.039 ;
     RECT  2.415 19.579 17.19 20.191 ;
     RECT  18.036 19.921 20.034 20.191 ;
     RECT  2.415 20.191 20.034 20.389 ;
     RECT  20.88 19.805 24.534 20.389 ;
     RECT  2.415 20.389 24.534 20.579 ;
     RECT  2.415 20.579 24.354 20.849 ;
     RECT  25.74 20.039 39.474 20.885 ;
     RECT  25.74 20.885 32.274 21.001 ;
     RECT  25.164 21.001 32.274 21.119 ;
     RECT  33.048 20.885 39.474 21.199 ;
     RECT  40.215 19.877 40.497 21.199 ;
     RECT  25.92 21.119 32.274 21.425 ;
     RECT  33.048 21.199 40.497 21.569 ;
     RECT  25.164 21.119 25.182 21.631 ;
     RECT  26.172 21.425 32.274 21.631 ;
     RECT  2.415 20.849 24.297 21.695 ;
     RECT  26.172 21.631 32.31 21.695 ;
     RECT  26.208 21.695 32.31 21.803 ;
     RECT  17.964 21.695 24.297 22.081 ;
     RECT  25.128 21.631 25.182 22.081 ;
     RECT  26.244 21.803 32.31 22.109 ;
     RECT  26.388 22.109 32.31 22.315 ;
     RECT  33.156 21.569 40.497 22.315 ;
     RECT  26.388 22.315 40.497 22.577 ;
     RECT  2.415 21.695 17.046 22.585 ;
     RECT  17.964 22.081 25.182 22.585 ;
     RECT  2.415 22.585 25.182 22.621 ;
     RECT  26.388 22.577 32.31 22.649 ;
     RECT  2.415 22.621 25.65 22.739 ;
     RECT  2.415 22.739 21.33 22.775 ;
     RECT  26.388 22.649 32.166 23.009 ;
     RECT  33.048 22.577 40.497 23.153 ;
     RECT  22.104 22.739 25.65 23.359 ;
     RECT  26.748 23.009 32.166 23.459 ;
     RECT  22.104 23.359 25.974 23.515 ;
     RECT  21.96 23.515 25.974 23.549 ;
     RECT  21.96 23.549 25.794 23.699 ;
     RECT  2.415 22.775 21.222 23.971 ;
     RECT  21.96 23.699 25.614 23.971 ;
     RECT  33.084 23.153 40.497 24.197 ;
     RECT  26.748 23.459 27.09 24.205 ;
     RECT  27.828 23.459 32.166 24.205 ;
     RECT  2.415 23.971 25.614 24.359 ;
     RECT  2.415 24.359 22.086 24.395 ;
     RECT  26.748 24.205 32.166 24.413 ;
     RECT  22.824 24.359 25.614 24.511 ;
     RECT  26.748 24.413 28.278 24.511 ;
     RECT  29.124 24.413 32.166 24.523 ;
     RECT  2.415 24.395 21.942 24.701 ;
     RECT  29.124 24.523 32.454 24.899 ;
     RECT  33.696 24.197 40.497 25.051 ;
     RECT  22.824 24.511 28.278 25.141 ;
     RECT  29.124 24.899 32.418 25.411 ;
     RECT  29.088 25.411 32.418 25.447 ;
     RECT  22.464 25.141 28.278 25.519 ;
     RECT  29.016 25.447 32.418 25.519 ;
     RECT  22.464 25.519 32.418 25.681 ;
     RECT  33.444 25.051 40.497 25.681 ;
     RECT  22.464 25.681 40.497 25.745 ;
     RECT  2.415 24.701 21.546 25.757 ;
     RECT  22.464 25.745 36.018 25.861 ;
     RECT  18.396 25.757 21.546 26.393 ;
     RECT  22.356 25.861 36.018 26.491 ;
     RECT  36.756 25.745 40.497 26.491 ;
     RECT  20.124 26.393 21.546 26.563 ;
     RECT  22.356 26.491 40.497 26.563 ;
     RECT  20.124 26.563 40.497 26.591 ;
     RECT  2.415 25.757 17.514 26.905 ;
     RECT  18.396 26.393 19.386 26.905 ;
     RECT  2.415 26.905 19.386 27.139 ;
     RECT  20.124 26.591 36.774 27.139 ;
     RECT  2.415 27.139 36.774 27.329 ;
     RECT  18.144 27.329 36.774 27.481 ;
     RECT  37.548 26.591 40.497 27.481 ;
     RECT  18.144 27.481 40.497 27.743 ;
     RECT  18.144 27.743 38.394 27.869 ;
     RECT  39.168 27.743 40.497 27.869 ;
     RECT  21.204 27.869 25.074 27.905 ;
     RECT  39.312 27.869 40.497 27.941 ;
     RECT  18.144 27.869 20.466 28.409 ;
     RECT  18.144 28.409 19.242 28.493 ;
     RECT  2.415 27.329 17.406 28.561 ;
     RECT  18.144 28.493 18.897 28.561 ;
     RECT  20.412 28.409 20.466 28.651 ;
     RECT  21.384 27.905 25.074 28.651 ;
     RECT  26.208 27.869 38.142 28.651 ;
     RECT  20.412 28.651 20.61 28.723 ;
     RECT  21.384 28.651 38.142 28.723 ;
     RECT  20.412 28.723 38.142 28.795 ;
     RECT  40.032 27.941 40.497 29.129 ;
     RECT  2.415 28.561 18.897 29.221 ;
     RECT  2.415 29.221 19.494 29.255 ;
     RECT  18.615 29.255 19.494 29.261 ;
     RECT  20.412 28.795 38.25 29.399 ;
     RECT  37.26 29.399 38.25 29.561 ;
     RECT  37.26 29.561 37.962 29.633 ;
     RECT  20.412 29.399 36.306 29.831 ;
     RECT  20.412 29.831 26.622 29.839 ;
     RECT  20.268 29.839 26.622 29.911 ;
     RECT  2.415 29.255 17.766 30.109 ;
     RECT  18.615 29.261 19.134 30.181 ;
     RECT  20.052 29.911 26.622 30.181 ;
     RECT  2.415 30.109 17.838 30.221 ;
     RECT  14.976 30.221 17.838 30.271 ;
     RECT  18.615 30.181 26.622 30.271 ;
     RECT  14.976 30.271 26.622 30.685 ;
     RECT  27.36 29.831 36.306 30.685 ;
     RECT  14.976 30.685 36.306 30.713 ;
     RECT  37.26 29.633 37.278 30.713 ;
     RECT  30.528 30.713 36.306 30.721 ;
     RECT  14.976 30.713 29.754 30.947 ;
     RECT  30.528 30.721 36.414 30.947 ;
     RECT  2.415 30.221 14.202 30.949 ;
     RECT  14.976 30.947 19.314 30.949 ;
     RECT  2.415 30.949 19.314 31.145 ;
     RECT  20.196 30.947 29.754 31.145 ;
     RECT  3.888 31.145 19.314 31.229 ;
     RECT  20.268 31.145 29.754 31.253 ;
     RECT  30.528 30.947 36.162 31.289 ;
     RECT  27.432 31.253 29.754 31.379 ;
     RECT  20.268 31.253 26.694 31.415 ;
     RECT  30.528 31.289 32.274 31.415 ;
     RECT  33.3 31.289 36.162 31.415 ;
     RECT  25.668 31.415 26.694 31.451 ;
     RECT  33.3 31.415 35.154 31.487 ;
     RECT  27.54 31.379 29.754 31.495 ;
     RECT  30.528 31.415 31.878 31.495 ;
     RECT  33.516 31.487 35.154 31.523 ;
     RECT  4.356 31.229 19.314 31.649 ;
     RECT  27.54 31.495 31.878 31.649 ;
     RECT  33.516 31.523 33.534 31.649 ;
     RECT  35.964 31.415 36.162 31.649 ;
     RECT  4.356 31.649 4.482 31.685 ;
     RECT  17.928 31.649 19.314 31.685 ;
     RECT  25.74 31.451 26.694 31.685 ;
     RECT  34.272 31.523 35.154 31.685 ;
     RECT  20.268 31.415 24.606 31.73 ;
     RECT  5.4 31.649 16.29 31.757 ;
     RECT  25.92 31.685 26.694 31.757 ;
     RECT  25.92 31.757 26.514 31.793 ;
     RECT  34.272 31.685 35.097 31.793 ;
     RECT  20.268 31.73 24.57 31.805 ;
     RECT  4.356 31.685 4.374 31.829 ;
     RECT  5.4 31.757 16.074 31.829 ;
     RECT  20.268 31.805 22.554 31.829 ;
     RECT  23.544 31.805 24.498 31.829 ;
     RECT  27.792 31.649 31.878 31.829 ;
     RECT  34.74 31.793 35.097 31.829 ;
     RECT  5.436 31.829 16.074 31.901 ;
     RECT  6.012 31.901 16.074 31.919 ;
     RECT  17.064 31.649 17.082 31.919 ;
     RECT  17.928 31.685 19.098 31.919 ;
     RECT  20.268 31.829 20.286 31.919 ;
     RECT  21.708 31.829 22.554 31.919 ;
     RECT  23.544 31.829 24.297 31.919 ;
     RECT  25.92 31.793 26.37 31.919 ;
     RECT  29.052 31.829 31.194 31.919 ;
     RECT  15.696 31.919 15.714 31.955 ;
     RECT  21.78 31.919 22.554 31.955 ;
     RECT  29.376 31.919 29.697 31.955 ;
     RECT  6.012 31.919 14.814 31.991 ;
     RECT  21.924 31.955 22.554 31.991 ;
     RECT  25.92 31.919 26.226 31.991 ;
     RECT  22.356 31.991 22.554 32.027 ;
     RECT  6.588 31.991 14.814 32.063 ;
     RECT  22.464 32.027 22.554 32.063 ;
     RECT  27.792 31.829 27.81 32.063 ;
     RECT  22.464 32.063 22.482 32.099 ;
     RECT  25.92 31.991 25.938 32.099 ;
     RECT  2.415 31.145 2.697 32.147 ;
     RECT  18.615 31.919 18.897 32.147 ;
     RECT  24.015 31.919 24.297 32.147 ;
     RECT  29.415 31.955 29.697 32.147 ;
     RECT  34.815 31.829 35.097 32.147 ;
     RECT  40.215 29.129 40.497 32.147 ;
     RECT  6.588 32.063 13.77 32.189 ;
     RECT  6.588 32.189 6.966 32.225 ;
     RECT  7.704 32.189 13.374 32.225 ;
     RECT  30.816 31.919 31.014 32.225 ;
     RECT  7.74 32.225 13.374 32.261 ;
     RECT  14.796 32.063 14.814 32.261 ;
     RECT  30.924 32.225 31.014 32.261 ;
     RECT  7.74 32.261 13.305 32.333 ;
     RECT  30.924 32.261 30.942 32.333 ;
     RECT  6.948 32.225 6.966 32.369 ;
     RECT  8.712 32.333 13.305 32.369 ;
     RECT  2.415 32.147 2.505 32.417 ;
     RECT  7.776 32.333 7.905 32.417 ;
     RECT  12.924 32.369 13.305 32.417 ;
     RECT  18.615 32.147 18.705 32.417 ;
     RECT  24.015 32.147 24.105 32.417 ;
     RECT  29.415 32.147 29.505 32.417 ;
     RECT  34.815 32.147 34.905 32.417 ;
     RECT  40.215 32.147 40.305 32.417 ;
     RECT  7.776 32.417 7.794 32.459 ;
     RECT  12.924 32.417 12.942 32.459 ;
     RECT  8.712 32.369 12.15 33.647 ;
     RECT  8.712 33.647 11.61 33.719 ;
     RECT  8.712 33.719 11.466 33.725 ;
     RECT  9 33.725 11.466 34.428 ;
    LAYER M4 ;
     RECT  0.156 14.88 0.227 15.192 ;
     RECT  0.181 16.608 2.401 16.632 ;
     RECT  0.227 15.024 2.408 15.192 ;
     RECT  2.401 16.368 2.408 16.632 ;
     RECT  2.408 2.148 2.512 32.412 ;
     RECT  2.512 2.256 2.704 32.142 ;
     RECT  2.704 2.256 3.017 4.104 ;
     RECT  2.704 14.736 3.203 18.456 ;
     RECT  3.203 16.416 3.233 18.456 ;
     RECT  2.704 20.544 3.377 21.144 ;
     RECT  2.704 28.992 3.443 30.84 ;
     RECT  2.704 26.784 3.449 27.048 ;
     RECT  3.203 15.216 3.539 15.384 ;
     RECT  3.377 20.544 3.587 21.048 ;
     RECT  3.233 16.416 3.628 17.64 ;
     RECT  3.539 15.216 3.665 15.288 ;
     RECT  2.704 5.76 3.697 6.312 ;
     RECT  2.704 22.704 3.697 22.728 ;
     RECT  3.449 26.784 3.773 26.808 ;
     RECT  3.443 29.04 3.781 30.84 ;
     RECT  3.665 15.216 3.809 15.24 ;
     RECT  3.017 2.784 3.925 4.104 ;
     RECT  3.697 5.424 3.925 6.312 ;
     RECT  3.925 2.784 3.971 6.312 ;
     RECT  3.781 29.04 4.025 31.224 ;
     RECT  3.805 8.544 4.093 8.568 ;
     RECT  2.704 9.696 4.093 9.72 ;
     RECT  3.971 5.712 4.129 6.312 ;
     RECT  2.704 10.8 4.129 11.16 ;
     RECT  2.704 12.48 4.129 12.504 ;
     RECT  4.093 8.544 4.133 9.72 ;
     RECT  4.129 10.8 4.201 12.504 ;
     RECT  3.697 22.704 4.205 22.872 ;
     RECT  4.201 10.8 4.345 13.128 ;
     RECT  4.129 5.712 4.349 7.08 ;
     RECT  3.971 4.656 4.493 4.68 ;
     RECT  4.133 8.544 4.547 9.24 ;
     RECT  4.025 29.952 4.549 31.224 ;
     RECT  4.349 6.288 4.601 7.08 ;
     RECT  4.601 6.528 4.637 7.08 ;
     RECT  4.547 9.216 4.637 9.24 ;
     RECT  4.345 10.224 4.709 13.128 ;
     RECT  4.549 29.952 4.709 31.704 ;
     RECT  4.205 22.848 4.789 22.872 ;
     RECT  2.704 24.528 4.789 24.552 ;
     RECT  3.587 20.592 4.835 21.048 ;
     RECT  4.709 10.224 4.853 12.408 ;
     RECT  4.853 10.224 4.997 10.344 ;
     RECT  4.853 11.952 5.123 12.408 ;
     RECT  4.709 29.952 5.137 29.976 ;
     RECT  4.637 6.528 5.141 6.84 ;
     RECT  4.835 20.592 5.141 20.616 ;
     RECT  5.141 6.528 5.177 6.648 ;
     RECT  5.123 11.952 5.177 11.976 ;
     RECT  4.777 25.824 5.18 25.848 ;
     RECT  3.628 16.608 5.249 17.64 ;
     RECT  5.137 29.088 5.249 29.976 ;
     RECT  5.18 25.824 5.267 26.76 ;
     RECT  5.249 29.088 5.267 29.112 ;
     RECT  4.789 22.848 5.317 24.552 ;
     RECT  5.267 25.824 5.317 25.848 ;
     RECT  4.709 31.68 5.425 31.704 ;
     RECT  5.077 15.456 5.533 15.48 ;
     RECT  5.317 22.848 5.605 25.848 ;
     RECT  3.971 2.784 5.641 2.808 ;
     RECT  5.605 22.224 5.645 25.848 ;
     RECT  5.641 2.784 5.785 3.624 ;
     RECT  4.997 10.32 5.789 10.344 ;
     RECT  5.645 23.808 5.933 25.848 ;
     RECT  5.785 2.784 5.948 4.152 ;
     RECT  5.948 2.784 5.989 4.536 ;
     RECT  5.989 2.784 6.001 5.16 ;
     RECT  4.885 14.4 6.109 14.424 ;
     RECT  5.533 15.408 6.109 15.48 ;
     RECT  5.249 16.608 6.113 17.256 ;
     RECT  6.109 14.4 6.181 15.48 ;
     RECT  6.181 13.536 6.437 15.48 ;
     RECT  5.933 23.808 6.437 25.32 ;
     RECT  6.397 9.264 6.505 9.288 ;
     RECT  5.177 6.624 6.577 6.648 ;
     RECT  6.325 7.728 6.577 7.752 ;
     RECT  6.113 16.608 6.581 17.064 ;
     RECT  6.325 12.48 6.685 12.504 ;
     RECT  6.437 14.4 6.721 15.48 ;
     RECT  6.581 16.608 6.721 16.632 ;
     RECT  5.857 30.432 6.793 30.456 ;
     RECT  5.425 31.68 6.793 31.896 ;
     RECT  6.793 30.432 6.853 31.896 ;
     RECT  6.001 2.784 7.153 5.256 ;
     RECT  6.577 6.624 7.153 7.752 ;
     RECT  5.645 22.224 7.153 22.248 ;
     RECT  6.437 23.808 7.369 24.504 ;
     RECT  6.685 11.952 7.513 12.504 ;
     RECT  6.853 30.432 7.513 31.992 ;
     RECT  7.513 11.424 7.585 12.504 ;
     RECT  6.721 14.4 7.585 16.632 ;
     RECT  7.513 30.096 7.621 31.992 ;
     RECT  7.441 26.64 7.669 26.664 ;
     RECT  7.153 2.784 7.729 7.752 ;
     RECT  6.505 8.736 7.729 9.288 ;
     RECT  7.669 26.544 7.765 26.664 ;
     RECT  7.669 27.936 7.765 27.96 ;
     RECT  7.729 2.784 7.808 9.288 ;
     RECT  7.585 11.424 7.808 13.128 ;
     RECT  7.585 14.208 7.808 16.632 ;
     RECT  7.369 20.064 7.808 20.088 ;
     RECT  7.153 21.504 7.808 22.248 ;
     RECT  7.369 23.328 7.808 24.504 ;
     RECT  7.765 26.544 7.808 27.96 ;
     RECT  7.621 30.048 7.808 31.992 ;
     RECT  7.808 2.148 7.912 32.412 ;
     RECT  7.912 2.418 8.104 32.142 ;
     RECT  8.104 2.784 8.165 9.288 ;
     RECT  8.165 2.784 8.273 9.192 ;
     RECT  8.104 10.848 8.339 12.552 ;
     RECT  8.104 21.264 8.381 21.528 ;
     RECT  8.104 18.144 8.531 20.088 ;
     RECT  8.104 13.824 8.705 14.232 ;
     RECT  7.693 0.528 8.953 0.552 ;
     RECT  8.705 14.208 9.029 14.232 ;
     RECT  8.953 0.192 9.059 0.552 ;
     RECT  8.531 19.344 9.109 20.088 ;
     RECT  8.381 21.264 9.109 21.432 ;
     RECT  9.109 19.344 9.155 21.432 ;
     RECT  8.701 33.696 9.157 33.72 ;
     RECT  9.157 33.648 9.277 33.72 ;
     RECT  8.273 3.12 9.313 9.192 ;
     RECT  8.339 10.848 9.313 11.784 ;
     RECT  8.104 22.8 9.349 32.088 ;
     RECT  9.277 33.648 9.385 33.768 ;
     RECT  9.313 3.12 9.445 11.784 ;
     RECT  9.059 0.432 9.491 0.552 ;
     RECT  9.385 33.072 9.539 33.768 ;
     RECT  9.349 22.752 9.557 32.088 ;
     RECT  9.539 33.072 9.557 33.672 ;
     RECT  9.155 20.544 9.569 21.432 ;
     RECT  9.445 2.88 9.605 11.784 ;
     RECT  8.104 15.456 9.635 16.968 ;
     RECT  9.457 1.728 9.637 1.752 ;
     RECT  9.605 2.88 9.637 11.496 ;
     RECT  9.589 13.008 9.637 13.032 ;
     RECT  9.557 22.752 9.637 33.672 ;
     RECT  9.569 21.12 9.961 21.432 ;
     RECT  9.637 22.704 9.961 33.672 ;
     RECT  9.635 15.648 10.019 16.968 ;
     RECT  9.637 1.728 10.211 11.496 ;
     RECT  10.019 16.608 10.249 16.968 ;
     RECT  8.531 18.144 10.433 18.168 ;
     RECT  10.211 2.16 10.595 11.496 ;
     RECT  9.491 0.48 10.741 0.552 ;
     RECT  10.741 0.288 10.753 0.552 ;
     RECT  10.595 2.208 10.789 11.496 ;
     RECT  10.753 0.192 10.825 0.552 ;
     RECT  9.961 21.12 10.885 33.672 ;
     RECT  10.825 0.192 10.931 0.6 ;
     RECT  10.789 2.208 10.933 11.544 ;
     RECT  9.637 12.528 10.933 13.032 ;
     RECT  10.885 21.12 11.005 33.72 ;
     RECT  11.005 21.12 11.117 33.768 ;
     RECT  11.117 23.088 11.123 33.768 ;
     RECT  10.249 16.608 11.185 17.064 ;
     RECT  11.123 23.088 11.225 33.72 ;
     RECT  11.225 23.76 11.261 33.72 ;
     RECT  11.261 23.76 11.267 33.096 ;
     RECT  11.267 33.072 11.363 33.096 ;
     RECT  11.185 16.608 11.477 17.88 ;
     RECT  10.931 0.192 11.507 0.552 ;
     RECT  9.155 19.344 11.513 19.368 ;
     RECT  10.933 2.208 11.605 13.032 ;
     RECT  11.605 1.728 11.617 13.032 ;
     RECT  11.617 1.728 11.653 13.656 ;
     RECT  11.267 23.76 11.657 32.088 ;
     RECT  11.477 16.608 11.945 17.064 ;
     RECT  11.653 1.728 11.981 13.896 ;
     RECT  11.653 15.408 12.401 15.432 ;
     RECT  11.117 21.12 12.445 21.432 ;
     RECT  11.507 0.288 12.469 0.552 ;
     RECT  12.445 20.304 12.469 21.432 ;
     RECT  12.193 22.8 12.469 22.824 ;
     RECT  12.469 0.192 12.517 0.552 ;
     RECT  11.981 1.728 12.517 13.656 ;
     RECT  12.517 0.192 12.659 13.656 ;
     RECT  11.945 16.608 12.949 16.872 ;
     RECT  12.659 0.192 12.953 0.552 ;
     RECT  12.953 0.288 12.995 0.552 ;
     RECT  12.659 1.728 13.097 13.656 ;
     RECT  13.097 1.92 13.208 13.656 ;
     RECT  12.401 14.88 13.208 15.432 ;
     RECT  12.949 16.608 13.208 17.112 ;
     RECT  12.805 18.192 13.208 18.216 ;
     RECT  12.908 19.2 13.208 19.224 ;
     RECT  12.469 20.304 13.208 22.824 ;
     RECT  11.657 24.192 13.208 32.088 ;
     RECT  12.995 0.288 13.235 0.312 ;
     RECT  13.208 1.92 13.312 32.412 ;
     RECT  13.312 1.92 13.504 32.142 ;
     RECT  13.504 20.304 13.565 20.52 ;
     RECT  13.504 21.696 13.565 32.04 ;
     RECT  13.565 22.032 13.673 32.04 ;
     RECT  13.504 1.92 13.709 13.416 ;
     RECT  13.673 22.752 14.14 32.04 ;
     RECT  13.709 2.064 14.213 13.416 ;
     RECT  14.213 3.984 14.435 13.416 ;
     RECT  14.435 4.032 14.465 13.416 ;
     RECT  14.14 22.752 14.483 31.944 ;
     RECT  14.483 22.752 14.645 29.304 ;
     RECT  14.483 30.48 14.645 31.944 ;
     RECT  14.645 22.752 14.716 27.96 ;
     RECT  13.504 14.784 14.732 14.808 ;
     RECT  13.504 16.608 14.732 16.872 ;
     RECT  14.716 23.568 14.753 27.96 ;
     RECT  14.645 29.04 14.753 29.304 ;
     RECT  14.732 14.496 14.773 14.808 ;
     RECT  14.732 15.984 14.773 16.872 ;
     RECT  14.773 14.496 14.819 16.872 ;
     RECT  14.465 4.464 14.821 13.416 ;
     RECT  14.819 16.608 14.821 16.872 ;
     RECT  14.213 2.064 14.861 2.808 ;
     RECT  13.565 20.496 14.861 20.52 ;
     RECT  14.753 23.568 14.897 27.816 ;
     RECT  14.897 23.616 14.933 27.72 ;
     RECT  14.753 29.232 14.933 29.304 ;
     RECT  14.645 30.48 15.005 31.704 ;
     RECT  14.933 23.616 15.059 27.48 ;
     RECT  14.819 15.456 15.077 15.48 ;
     RECT  14.821 4.464 15.221 13.608 ;
     RECT  15.221 12.72 15.395 13.608 ;
     RECT  15.059 23.664 15.395 27.48 ;
     RECT  15.221 4.464 15.437 11.736 ;
     RECT  14.821 16.608 15.577 17.64 ;
     RECT  15.005 30.912 15.689 31.704 ;
     RECT  15.437 7.2 15.761 11.736 ;
     RECT  15.437 4.464 15.797 6.024 ;
     RECT  15.145 19.344 15.833 19.368 ;
     RECT  14.861 2.208 15.865 2.808 ;
     RECT  15.577 16.608 15.971 18.264 ;
     RECT  15.395 24.144 16.045 27.48 ;
     RECT  14.933 29.28 16.045 29.304 ;
     RECT  15.761 7.92 16.085 11.736 ;
     RECT  15.865 2.208 16.193 3.432 ;
     RECT  15.797 6 16.265 6.024 ;
     RECT  16.045 24.144 16.268 29.304 ;
     RECT  15.395 13.104 16.309 13.608 ;
     RECT  16.297 14.832 16.309 14.856 ;
     RECT  16.268 24.144 16.309 29.4 ;
     RECT  15.689 30.912 16.309 30.936 ;
     RECT  16.193 2.832 16.333 3.432 ;
     RECT  15.797 4.464 16.333 4.728 ;
     RECT  16.085 7.92 16.373 9.816 ;
     RECT  16.309 13.104 16.381 14.856 ;
     RECT  16.373 7.92 16.403 9.096 ;
     RECT  16.381 13.104 16.409 14.808 ;
     RECT  16.333 2.832 16.417 4.728 ;
     RECT  16.309 24.144 16.441 30.936 ;
     RECT  16.441 23.664 16.481 30.936 ;
     RECT  16.481 28.416 16.805 30.936 ;
     RECT  16.805 28.608 16.837 30.936 ;
     RECT  16.837 28.608 16.877 30.984 ;
     RECT  16.481 23.664 16.985 27.24 ;
     RECT  16.985 23.664 17.053 26.856 ;
     RECT  15.971 16.608 17.089 17.64 ;
     RECT  17.053 23.376 17.129 26.856 ;
     RECT  16.877 30.768 17.129 30.984 ;
     RECT  17.089 19.344 17.161 19.368 ;
     RECT  17.129 23.376 17.165 26.76 ;
     RECT  16.085 10.848 17.197 11.736 ;
     RECT  16.117 20.496 17.201 20.52 ;
     RECT  17.165 23.376 17.201 26.28 ;
     RECT  16.417 2.832 17.209 3.432 ;
     RECT  16.409 13.104 17.345 13.656 ;
     RECT  16.409 14.784 17.389 14.808 ;
     RECT  16.403 7.92 17.521 8.952 ;
     RECT  17.521 7.92 17.525 9.624 ;
     RECT  17.516 15.12 17.557 15.144 ;
     RECT  17.197 10.704 17.603 11.736 ;
     RECT  17.557 15.12 17.603 15.48 ;
     RECT  17.345 13.104 17.701 13.128 ;
     RECT  17.161 18.816 17.701 19.368 ;
     RECT  17.525 7.92 17.881 8.568 ;
     RECT  15.361 22.176 17.953 22.2 ;
     RECT  17.603 15.456 17.989 15.48 ;
     RECT  17.089 16.608 17.989 17.832 ;
     RECT  16.417 4.704 18.133 4.728 ;
     RECT  17.989 15.456 18.181 17.832 ;
     RECT  17.701 18.816 18.181 20.328 ;
     RECT  17.953 21.792 18.229 22.2 ;
     RECT  17.201 23.376 18.229 24.552 ;
     RECT  18.133 4.704 18.349 5.688 ;
     RECT  17.201 25.728 18.421 26.28 ;
     RECT  16.877 28.608 18.421 29.736 ;
     RECT  17.129 30.768 18.421 30.936 ;
     RECT  17.209 2.88 18.469 3.432 ;
     RECT  18.349 4.704 18.469 5.832 ;
     RECT  17.881 7.104 18.493 8.568 ;
     RECT  17.525 9.6 18.493 9.624 ;
     RECT  18.421 25.728 18.493 26.808 ;
     RECT  18.493 25.728 18.565 26.856 ;
     RECT  18.469 2.88 18.608 5.832 ;
     RECT  18.493 7.104 18.608 9.624 ;
     RECT  17.603 10.704 18.608 10.92 ;
     RECT  17.701 12.72 18.608 13.128 ;
     RECT  18.181 15.456 18.608 20.328 ;
     RECT  18.229 21.408 18.608 24.552 ;
     RECT  18.565 25.728 18.608 26.904 ;
     RECT  18.421 28.608 18.608 30.936 ;
     RECT  18.608 2.148 18.712 32.412 ;
     RECT  18.712 2.418 18.904 32.142 ;
     RECT  18.904 2.592 18.965 8.856 ;
     RECT  18.904 20.064 19.073 21.816 ;
     RECT  18.904 10.848 19.181 11.976 ;
     RECT  18.904 24.096 19.217 26.904 ;
     RECT  18.904 28.464 19.283 29.304 ;
     RECT  18.904 30.336 19.283 31.656 ;
     RECT  19.283 30.384 19.325 31.656 ;
     RECT  19.217 24.096 19.397 26.856 ;
     RECT  19.073 20.544 19.469 21.816 ;
     RECT  19.397 24.096 19.497 25.944 ;
     RECT  19.325 30.384 19.505 30.936 ;
     RECT  19.505 30.912 19.649 30.936 ;
     RECT  18.965 2.592 19.756 6.264 ;
     RECT  18.904 14.448 19.973 15.48 ;
     RECT  18.965 8.832 20.101 8.856 ;
     RECT  19.756 5.04 20.149 6.264 ;
     RECT  18.965 7.344 20.149 7.368 ;
     RECT  20.149 5.04 20.153 7.368 ;
     RECT  19.181 10.848 20.153 11.4 ;
     RECT  19.469 20.544 20.261 21.672 ;
     RECT  19.973 14.88 20.329 15.48 ;
     RECT  20.329 14.88 20.369 15.576 ;
     RECT  18.904 16.608 20.401 16.872 ;
     RECT  19.283 29.232 20.437 29.304 ;
     RECT  20.437 28.416 20.579 29.304 ;
     RECT  20.101 8.832 20.581 9.528 ;
     RECT  19.756 2.592 20.585 3.432 ;
     RECT  20.585 3.408 20.621 3.432 ;
     RECT  20.369 15.456 20.621 15.576 ;
     RECT  20.401 16.608 20.621 17.112 ;
     RECT  20.579 28.656 20.621 29.304 ;
     RECT  19.497 24.912 20.657 25.944 ;
     RECT  20.533 27.312 20.693 27.336 ;
     RECT  20.657 24.912 20.725 25.704 ;
     RECT  20.581 8.736 20.765 9.528 ;
     RECT  20.153 5.856 20.801 7.368 ;
     RECT  20.261 20.544 20.801 21.432 ;
     RECT  20.765 9.504 20.945 9.528 ;
     RECT  20.621 15.552 20.945 15.576 ;
     RECT  20.725 12.912 20.965 12.936 ;
     RECT  20.941 13.968 20.965 13.992 ;
     RECT  20.965 12.912 21.011 13.992 ;
     RECT  19.969 23.088 21.053 23.112 ;
     RECT  20.621 16.608 21.061 16.872 ;
     RECT  20.801 5.856 21.089 6.648 ;
     RECT  20.621 29.28 21.193 29.304 ;
     RECT  21.089 5.856 21.197 6.12 ;
     RECT  20.833 7.728 21.197 7.752 ;
     RECT  21.011 13.44 21.269 13.992 ;
     RECT  21.193 29.28 21.373 29.832 ;
     RECT  21.061 15.984 21.377 16.872 ;
     RECT  20.725 24.48 21.443 25.704 ;
     RECT  21.197 5.856 21.485 5.88 ;
     RECT  21.443 25.152 21.485 25.704 ;
     RECT  21.373 29.28 21.661 29.928 ;
     RECT  21.553 31.152 21.697 31.176 ;
     RECT  20.801 20.832 21.841 21.432 ;
     RECT  21.661 29.28 21.949 29.976 ;
     RECT  21.949 29.04 22.021 29.976 ;
     RECT  21.841 9.12 22.057 9.144 ;
     RECT  21.409 18.816 22.169 18.84 ;
     RECT  20.153 11.376 22.173 11.4 ;
     RECT  22.021 14.016 22.193 14.04 ;
     RECT  22.021 7.296 22.201 7.32 ;
     RECT  22.057 9.12 22.259 9.96 ;
     RECT  22.193 14.016 22.259 14.856 ;
     RECT  21.949 23.52 22.259 23.544 ;
     RECT  21.377 16.848 22.273 16.872 ;
     RECT  22.259 9.12 22.277 9.144 ;
     RECT  22.259 14.832 22.277 14.856 ;
     RECT  21.085 22.464 22.349 22.488 ;
     RECT  22.021 29.04 22.417 30.12 ;
     RECT  21.697 31.152 22.417 31.8 ;
     RECT  22.213 12.912 22.457 12.936 ;
     RECT  21.841 5.184 22.597 5.208 ;
     RECT  21.841 20.496 22.597 21.432 ;
     RECT  22.597 4.608 22.705 5.208 ;
     RECT  22.201 6.816 22.705 7.32 ;
     RECT  22.597 20.496 22.777 21.672 ;
     RECT  22.777 20.112 22.817 21.672 ;
     RECT  21.485 25.68 22.961 25.704 ;
     RECT  22.817 20.112 22.997 20.136 ;
     RECT  22.813 3.12 23.173 3.144 ;
     RECT  22.705 4.608 23.173 7.32 ;
     RECT  23.461 8.976 23.533 9 ;
     RECT  22.273 16.848 23.533 17.64 ;
     RECT  23.173 2.832 23.569 7.32 ;
     RECT  23.533 8.784 23.569 9 ;
     RECT  23.569 2.832 23.677 9 ;
     RECT  23.677 2.832 23.749 9.576 ;
     RECT  22.597 23.952 23.749 23.976 ;
     RECT  23.749 2.832 24.008 10.152 ;
     RECT  22.173 11.136 24.008 11.4 ;
     RECT  23.533 16.848 24.008 18.456 ;
     RECT  22.817 21.408 24.008 21.672 ;
     RECT  23.749 23.952 24.008 24.408 ;
     RECT  23.245 26.208 24.008 26.232 ;
     RECT  22.417 29.04 24.008 31.8 ;
     RECT  24.008 2.148 24.112 32.412 ;
     RECT  24.112 2.418 24.304 32.142 ;
     RECT  24.304 2.64 24.329 7.08 ;
     RECT  24.304 12.864 24.437 13.176 ;
     RECT  24.329 5.568 24.473 7.08 ;
     RECT  24.437 13.056 24.473 13.176 ;
     RECT  24.304 9.072 24.509 10.152 ;
     RECT  24.509 9.072 24.545 9.24 ;
     RECT  24.304 29.28 24.581 31.8 ;
     RECT  24.581 29.28 24.617 31.704 ;
     RECT  24.304 18.432 24.689 18.456 ;
     RECT  24.473 5.616 24.797 7.08 ;
     RECT  24.617 29.28 24.797 31.224 ;
     RECT  24.545 9.216 24.833 9.24 ;
     RECT  24.797 6 25.036 7.08 ;
     RECT  24.329 2.64 25.085 4.296 ;
     RECT  24.473 13.056 25.157 13.08 ;
     RECT  24.304 16.848 25.157 17.112 ;
     RECT  24.304 24.288 25.285 24.936 ;
     RECT  25.285 23.664 25.331 24.936 ;
     RECT  24.304 26.496 25.481 27.768 ;
     RECT  25.331 23.664 25.549 23.928 ;
     RECT  25.549 23.376 25.612 23.928 ;
     RECT  25.612 23.376 25.633 23.688 ;
     RECT  25.481 26.496 25.733 26.808 ;
     RECT  25.036 6 25.769 6.936 ;
     RECT  25.801 20.4 25.909 20.424 ;
     RECT  24.304 21.408 25.909 21.432 ;
     RECT  24.797 29.808 25.909 31.224 ;
     RECT  25.873 18.864 25.981 18.888 ;
     RECT  25.909 20.4 25.981 21.432 ;
     RECT  25.909 29.808 25.985 31.752 ;
     RECT  25.916 10.32 26.003 10.344 ;
     RECT  24.304 11.328 26.003 11.784 ;
     RECT  25.331 24.912 26.017 24.936 ;
     RECT  24.304 15.696 26.06 15.72 ;
     RECT  25.157 16.848 26.06 17.064 ;
     RECT  25.333 28.8 26.101 28.824 ;
     RECT  25.985 29.808 26.101 29.832 ;
     RECT  25.769 6 26.129 6.888 ;
     RECT  26.06 15.696 26.147 17.064 ;
     RECT  26.101 28.8 26.147 29.832 ;
     RECT  25.085 2.64 26.165 3.672 ;
     RECT  25.981 18.864 26.233 21.432 ;
     RECT  26.165 2.64 26.273 3.336 ;
     RECT  26.147 15.696 26.629 15.72 ;
     RECT  25.957 8.976 26.665 9 ;
     RECT  26.233 18.288 26.669 21.432 ;
     RECT  26.017 24.912 26.701 25.272 ;
     RECT  25.733 26.496 26.701 26.52 ;
     RECT  25.985 30.816 26.705 31.752 ;
     RECT  26.147 16.848 26.737 17.064 ;
     RECT  26.629 14.88 26.741 15.72 ;
     RECT  25.633 23.664 26.773 23.688 ;
     RECT  26.701 24.912 26.773 26.52 ;
     RECT  26.773 23.664 26.813 26.52 ;
     RECT  26.669 18.384 26.881 21.432 ;
     RECT  26.881 18.384 26.885 21.576 ;
     RECT  26.885 18.384 26.921 18.888 ;
     RECT  26.885 19.968 26.989 21.576 ;
     RECT  26.129 6 27.073 6.84 ;
     RECT  26.665 8.976 27.317 9.24 ;
     RECT  27.073 6 27.349 6.312 ;
     RECT  26.147 29.52 27.389 29.832 ;
     RECT  27.349 5.664 27.395 6.312 ;
     RECT  26.813 24.384 27.445 26.52 ;
     RECT  27.445 24.384 27.493 27.144 ;
     RECT  26.705 30.816 27.5 31.176 ;
     RECT  26.273 2.64 27.521 3.144 ;
     RECT  27.521 2.64 27.587 3.432 ;
     RECT  26.809 13.2 27.589 13.224 ;
     RECT  26.737 16.848 27.635 17.112 ;
     RECT  27.395 5.664 27.637 6.024 ;
     RECT  26.921 18.384 27.637 18.456 ;
     RECT  26.989 19.968 27.641 21.672 ;
     RECT  27.5 30.528 27.673 31.176 ;
     RECT  27.493 24.384 27.709 27.384 ;
     RECT  27.641 20.736 27.713 21.672 ;
     RECT  27.587 2.832 27.749 3.432 ;
     RECT  27.589 13.056 27.781 13.224 ;
     RECT  27.389 29.52 27.817 29.544 ;
     RECT  27.673 30.528 27.857 31.368 ;
     RECT  26.003 11.376 27.925 11.784 ;
     RECT  27.713 20.736 27.965 21.432 ;
     RECT  27.925 11.376 27.971 12.024 ;
     RECT  26.741 15.696 28.117 15.72 ;
     RECT  27.637 5.04 28.253 6.024 ;
     RECT  27.313 23.04 28.253 23.064 ;
     RECT  27.709 24.384 28.259 28.008 ;
     RECT  28.259 26.256 28.3 28.008 ;
     RECT  28.3 26.496 28.393 28.008 ;
     RECT  27.817 29.088 28.393 29.544 ;
     RECT  27.857 30.864 28.393 31.368 ;
     RECT  28.393 30.864 28.537 31.656 ;
     RECT  27.781 13.056 28.933 13.32 ;
     RECT  27.637 17.616 28.933 18.456 ;
     RECT  28.717 19.584 28.933 19.608 ;
     RECT  28.933 13.056 28.969 13.416 ;
     RECT  28.117 15.696 28.969 16.584 ;
     RECT  28.393 26.496 29.005 29.544 ;
     RECT  27.971 12 29.077 12.024 ;
     RECT  28.969 13.056 29.077 13.848 ;
     RECT  29.005 26.496 29.149 29.784 ;
     RECT  28.253 6 29.257 6.024 ;
     RECT  28.717 21.504 29.257 21.528 ;
     RECT  28.969 15.504 29.269 16.584 ;
     RECT  28.933 17.616 29.269 19.608 ;
     RECT  29.257 6 29.365 6.84 ;
     RECT  27.749 3.12 29.408 3.432 ;
     RECT  29.365 6 29.408 7.128 ;
     RECT  27.317 8.976 29.408 9 ;
     RECT  29.077 12 29.408 13.848 ;
     RECT  29.269 15.504 29.408 19.608 ;
     RECT  29.257 21.408 29.408 21.528 ;
     RECT  28.259 24.384 29.408 24.744 ;
     RECT  29.149 26.496 29.408 29.832 ;
     RECT  28.537 30.864 29.408 31.704 ;
     RECT  29.408 2.148 29.512 32.412 ;
     RECT  29.512 2.418 29.704 32.142 ;
     RECT  29.704 16.848 29.801 19.272 ;
     RECT  29.704 24.384 29.873 24.744 ;
     RECT  29.704 11.232 29.981 12.264 ;
     RECT  29.704 3.12 30.125 3.192 ;
     RECT  29.801 16.944 30.197 19.272 ;
     RECT  30.197 16.944 30.323 18.6 ;
     RECT  29.704 22.8 30.323 22.824 ;
     RECT  29.704 13.392 30.377 13.896 ;
     RECT  29.873 24.72 30.413 24.744 ;
     RECT  29.704 6 30.557 7.656 ;
     RECT  30.377 13.536 30.629 13.896 ;
     RECT  30.323 16.944 30.665 18.456 ;
     RECT  29.704 14.88 30.737 15.864 ;
     RECT  29.704 27.888 30.769 29.688 ;
     RECT  29.704 30.768 30.769 31.704 ;
     RECT  30.769 27.888 30.989 31.704 ;
     RECT  30.985 25.632 31.069 25.656 ;
     RECT  30.557 6 31.097 6.84 ;
     RECT  30.733 23.088 31.097 23.112 ;
     RECT  30.989 27.888 31.097 31.32 ;
     RECT  30.125 3.168 31.201 3.192 ;
     RECT  31.201 2.784 31.417 3.192 ;
     RECT  30.629 13.536 31.417 13.656 ;
     RECT  29.981 11.232 31.529 11.592 ;
     RECT  29.704 20.304 31.601 20.424 ;
     RECT  31.601 20.304 31.673 20.376 ;
     RECT  30.737 15.456 31.889 15.864 ;
     RECT  31.417 2.784 31.961 3.288 ;
     RECT  31.097 28.32 31.961 31.32 ;
     RECT  31.673 20.304 32.069 20.328 ;
     RECT  30.665 18.432 32.101 18.456 ;
     RECT  31.529 11.232 32.213 11.256 ;
     RECT  31.889 15.456 32.249 15.48 ;
     RECT  31.961 31.104 32.285 31.32 ;
     RECT  32.101 18.144 32.396 18.456 ;
     RECT  31.417 13.488 32.465 13.656 ;
     RECT  32.396 18.144 32.483 18.984 ;
     RECT  31.961 28.32 32.713 30.12 ;
     RECT  32.461 10.176 32.857 10.2 ;
     RECT  32.857 10.08 32.965 10.2 ;
     RECT  32.713 28.272 32.972 30.12 ;
     RECT  29.704 26.64 33.013 26.664 ;
     RECT  32.972 27.936 33.013 30.12 ;
     RECT  33.013 26.64 33.059 30.12 ;
     RECT  32.483 18.144 33.068 18.456 ;
     RECT  32.965 9.888 33.109 10.2 ;
     RECT  32.465 13.488 33.149 13.512 ;
     RECT  30.665 16.944 33.149 17.064 ;
     RECT  33.068 18.096 33.155 18.456 ;
     RECT  33.059 26.64 33.257 27.24 ;
     RECT  29.704 21.408 33.325 21.528 ;
     RECT  33.397 23.52 33.433 23.544 ;
     RECT  32.425 24.528 33.433 24.552 ;
     RECT  33.433 23.52 33.469 24.552 ;
     RECT  33.149 17.04 33.473 17.064 ;
     RECT  33.109 9.792 33.509 10.2 ;
     RECT  33.325 21.408 33.541 22.008 ;
     RECT  33.059 28.272 33.541 30.12 ;
     RECT  32.285 31.104 33.541 31.128 ;
     RECT  33.541 28.272 33.545 31.128 ;
     RECT  33.509 9.888 33.581 10.2 ;
     RECT  33.581 10.08 33.653 10.2 ;
     RECT  31.961 2.784 33.793 3.192 ;
     RECT  31.097 6 33.793 6.024 ;
     RECT  33.541 21.36 33.937 22.008 ;
     RECT  33.937 10.368 33.973 10.392 ;
     RECT  33.793 5.856 34.189 6.024 ;
     RECT  33.793 2.784 34.513 3.336 ;
     RECT  34.189 4.944 34.513 6.024 ;
     RECT  33.469 23.376 34.645 24.552 ;
     RECT  33.937 21.12 34.765 22.008 ;
     RECT  34.513 2.784 34.808 6.024 ;
     RECT  33.973 10.368 34.808 11.064 ;
     RECT  33.361 14.832 34.808 14.856 ;
     RECT  34.765 16.368 34.808 16.392 ;
     RECT  33.155 18.144 34.808 18.456 ;
     RECT  33.577 19.584 34.808 19.608 ;
     RECT  34.765 21.12 34.808 22.056 ;
     RECT  34.645 23.376 34.808 25.224 ;
     RECT  33.257 26.64 34.808 27.144 ;
     RECT  33.545 28.272 34.808 28.44 ;
     RECT  33.545 29.568 34.808 31.128 ;
     RECT  34.808 2.148 34.912 32.412 ;
     RECT  34.912 2.418 35.104 32.142 ;
     RECT  35.104 5.184 35.165 6.264 ;
     RECT  35.104 3.936 35.219 4.2 ;
     RECT  35.165 5.232 35.219 6.264 ;
     RECT  35.104 9.888 35.237 12.312 ;
     RECT  35.219 4.176 35.345 4.2 ;
     RECT  35.237 10.944 35.381 12.312 ;
     RECT  35.104 26.64 35.381 29.64 ;
     RECT  35.104 14.928 35.417 14.952 ;
     RECT  35.104 18.144 35.507 25.224 ;
     RECT  35.381 10.992 35.525 12.312 ;
     RECT  35.507 18.576 35.603 25.224 ;
     RECT  35.525 11.904 35.741 12.312 ;
     RECT  35.381 26.64 35.795 29.592 ;
     RECT  35.219 5.232 35.813 5.256 ;
     RECT  35.741 12.096 35.849 12.312 ;
     RECT  35.795 26.64 35.957 29.208 ;
     RECT  35.957 26.64 36.101 27.912 ;
     RECT  35.849 12.288 36.137 12.312 ;
     RECT  35.603 21.168 36.209 21.672 ;
     RECT  36.101 26.64 36.209 27.144 ;
     RECT  35.603 18.576 36.317 20.184 ;
     RECT  35.104 30.816 36.467 31.608 ;
     RECT  36.209 26.64 36.508 26.76 ;
     RECT  36.209 21.168 36.533 21.192 ;
     RECT  35.603 22.752 36.569 25.224 ;
     RECT  36.317 18.576 36.605 18.6 ;
     RECT  35.237 9.888 36.713 9.912 ;
     RECT  36.569 22.752 36.713 23.064 ;
     RECT  36.569 24.096 36.785 25.224 ;
     RECT  35.104 2.784 36.893 2.808 ;
     RECT  36.785 24.24 36.929 25.224 ;
     RECT  36.317 20.16 37.073 20.184 ;
     RECT  36.929 25.2 37.145 25.224 ;
     RECT  35.957 29.184 37.177 29.208 ;
     RECT  35.104 16.368 37.217 16.392 ;
     RECT  37.177 29.184 37.388 29.256 ;
     RECT  36.817 26.256 37.393 26.28 ;
     RECT  36.637 3.936 37.429 3.96 ;
     RECT  37.429 3.36 37.469 3.96 ;
     RECT  37.388 28.992 37.475 29.256 ;
     RECT  35.219 6.24 37.477 6.264 ;
     RECT  37.469 3.36 37.523 3.384 ;
     RECT  37.393 26.208 37.573 26.28 ;
     RECT  37.321 27.648 37.573 27.672 ;
     RECT  37.573 26.208 37.721 27.672 ;
     RECT  37.825 18.768 37.933 18.792 ;
     RECT  37.475 29.232 38.009 29.256 ;
     RECT  37.825 11.952 38.149 11.976 ;
     RECT  37.477 5.328 38.185 6.264 ;
     RECT  37.721 26.208 38.261 27.384 ;
     RECT  35.104 7.968 38.293 7.992 ;
     RECT  38.252 10.032 38.293 10.056 ;
     RECT  37.933 18.768 38.293 19.368 ;
     RECT  38.293 7.968 38.348 8.424 ;
     RECT  38.185 5.328 38.435 6.84 ;
     RECT  38.435 5.328 38.473 6.024 ;
     RECT  38.348 7.824 38.509 8.424 ;
     RECT  38.293 10.032 38.509 10.2 ;
     RECT  38.509 7.824 38.585 10.2 ;
     RECT  38.261 27.216 38.585 27.24 ;
     RECT  38.293 18.432 38.617 19.368 ;
     RECT  38.585 9.312 38.621 10.2 ;
     RECT  38.617 18.192 38.729 19.368 ;
     RECT  38.149 11.952 38.765 12.744 ;
     RECT  38.473 5.04 38.771 6.024 ;
     RECT  38.765 11.952 38.801 11.976 ;
     RECT  38.261 26.208 38.837 26.232 ;
     RECT  36.713 23.04 38.945 23.064 ;
     RECT  38.729 18.192 38.981 18.792 ;
     RECT  38.689 20.544 39.053 20.568 ;
     RECT  38.437 21.552 39.053 21.576 ;
     RECT  38.771 5.28 39.089 6.024 ;
     RECT  39.74 14.064 39.769 14.088 ;
     RECT  38.221 15.456 39.829 15.48 ;
     RECT  39.089 6 40.208 6.024 ;
     RECT  39.373 7.68 40.208 7.704 ;
     RECT  38.621 10.176 40.208 10.2 ;
     RECT  39.769 14.064 40.208 14.232 ;
     RECT  39.829 15.456 40.208 16.008 ;
     RECT  38.981 18.768 40.208 18.792 ;
     RECT  40.208 2.148 40.312 32.412 ;
     RECT  40.312 2.418 40.504 32.142 ;
    LAYER M5 ;
     RECT  9.024 0.144 13.512 0.227 ;
     RECT  9.168 0.227 13.512 0.563 ;
     RECT  9.6 0.563 13.512 1.763 ;
     RECT  9.648 1.763 13.512 2.101 ;
     RECT  2.4 2.137 2.52 2.151 ;
     RECT  7.8 2.137 7.92 2.151 ;
     RECT  18.6 2.137 18.72 2.151 ;
     RECT  24 2.137 24.12 2.151 ;
     RECT  29.4 2.137 29.52 2.151 ;
     RECT  34.8 2.137 34.92 2.151 ;
     RECT  40.2 2.137 40.32 2.151 ;
     RECT  9.648 2.101 13.608 2.197 ;
     RECT  2.4 2.151 2.712 2.245 ;
     RECT  9.648 2.197 13.656 2.629 ;
     RECT  24 2.151 24.312 2.629 ;
     RECT  24 2.629 24.984 2.821 ;
     RECT  9.648 2.629 14.424 2.869 ;
     RECT  23.232 2.821 24.984 3.203 ;
     RECT  7.8 2.151 8.112 3.397 ;
     RECT  18.6 2.151 18.912 3.397 ;
     RECT  17.136 2.821 17.16 3.443 ;
     RECT  27.552 2.629 27.576 3.443 ;
     RECT  7.68 3.397 8.112 3.541 ;
     RECT  9.456 2.869 14.424 3.541 ;
     RECT  7.68 3.541 14.424 3.637 ;
     RECT  23.328 3.203 24.984 3.827 ;
     RECT  34.8 2.151 35.112 3.925 ;
     RECT  7.488 3.637 14.424 4.019 ;
     RECT  2.4 2.245 2.856 4.115 ;
     RECT  18.48 3.397 18.912 4.115 ;
     RECT  18.6 4.115 18.912 4.261 ;
     RECT  7.488 4.019 13.944 4.405 ;
     RECT  34.8 3.925 35.208 4.837 ;
     RECT  18.6 4.261 19.704 5.075 ;
     RECT  6 3.589 6.024 5.171 ;
     RECT  23.328 3.827 24.312 5.171 ;
     RECT  24 5.171 24.312 5.605 ;
     RECT  27.936 5.077 27.96 5.653 ;
     RECT  3.936 2.773 3.96 5.747 ;
     RECT  34.704 4.837 35.208 5.891 ;
     RECT  37.488 3.349 37.512 5.989 ;
     RECT  38.736 5.029 38.76 5.989 ;
     RECT  37.488 5.989 38.76 6.035 ;
     RECT  24 5.605 24.744 6.085 ;
     RECT  18.6 5.075 19.032 6.275 ;
     RECT  37.488 6.035 38.424 6.275 ;
     RECT  27.36 5.653 27.96 6.805 ;
     RECT  24 6.085 24.984 7.091 ;
     RECT  7.44 4.405 13.944 7.189 ;
     RECT  7.44 7.189 14.232 7.717 ;
     RECT  38.4 6.275 38.424 7.859 ;
     RECT  6.816 7.717 14.232 8.003 ;
     RECT  34.8 5.891 35.208 8.003 ;
     RECT  6.816 8.003 14.184 8.771 ;
     RECT  16.368 3.925 16.392 9.107 ;
     RECT  4.512 8.533 4.536 9.251 ;
     RECT  27.024 6.805 27.96 9.251 ;
     RECT  7.68 8.771 14.184 9.491 ;
     RECT  20.112 8.821 20.136 9.539 ;
     RECT  40.2 2.151 40.512 10.165 ;
     RECT  38.304 8.389 38.328 10.211 ;
     RECT  11.088 9.491 14.184 10.355 ;
     RECT  11.184 10.355 14.184 10.883 ;
     RECT  7.68 9.491 10.008 10.979 ;
     RECT  22.224 9.925 22.248 11.171 ;
     RECT  25.968 8.965 25.992 11.363 ;
     RECT  7.68 10.979 8.328 11.459 ;
     RECT  11.376 10.883 14.184 11.653 ;
     RECT  11.376 11.653 14.28 11.699 ;
     RECT  27.936 9.251 27.96 12.035 ;
     RECT  11.664 11.699 14.28 12.373 ;
     RECT  15.36 9.061 15.384 12.373 ;
     RECT  7.8 11.459 8.328 12.517 ;
     RECT  7.68 12.517 8.328 12.563 ;
     RECT  11.664 12.373 15.384 12.755 ;
     RECT  29.4 2.151 29.712 12.997 ;
     RECT  7.68 12.563 8.112 13.139 ;
     RECT  11.664 12.755 15.144 13.139 ;
     RECT  11.664 13.139 14.28 13.427 ;
     RECT  20.976 12.901 21 13.429 ;
     RECT  20.976 13.429 21.096 13.475 ;
     RECT  11.664 13.427 13.512 13.907 ;
     RECT  39.792 10.165 40.512 14.099 ;
     RECT  2.4 4.115 2.712 14.725 ;
     RECT  17.568 8.485 17.592 14.773 ;
     RECT  16.32 13.957 16.344 14.867 ;
     RECT  22.224 12.901 22.248 14.867 ;
     RECT  12.096 13.907 13.512 14.915 ;
     RECT  2.4 14.725 3.192 15.349 ;
     RECT  17.328 14.773 17.592 15.445 ;
     RECT  18.6 6.275 18.912 15.445 ;
     RECT  5.088 12.373 5.112 15.491 ;
     RECT  9.6 10.979 10.008 15.491 ;
     RECT  9.984 15.491 10.008 15.683 ;
     RECT  27.6 13.045 27.624 15.685 ;
     RECT  14.784 14.485 14.808 16.019 ;
     RECT  21.072 13.475 21.096 16.019 ;
     RECT  39.84 14.099 40.512 16.019 ;
     RECT  27.6 15.685 28.152 16.259 ;
     RECT  2.4 15.349 3.528 16.405 ;
     RECT  0.192 14.869 0.216 16.643 ;
     RECT  12.096 14.915 12.12 16.741 ;
     RECT  13.2 14.915 13.512 16.741 ;
     RECT  12.096 16.741 13.512 16.787 ;
     RECT  27.6 16.259 27.624 16.837 ;
     RECT  29.28 12.997 29.712 16.883 ;
     RECT  29.4 16.883 29.712 17.605 ;
     RECT  33.12 17.029 33.144 18.131 ;
     RECT  34.8 8.003 35.112 18.133 ;
     RECT  15.936 17.173 15.96 18.275 ;
     RECT  7.8 13.139 8.112 18.757 ;
     RECT  38.88 18.613 38.904 18.803 ;
     RECT  17.328 15.445 18.912 18.851 ;
     RECT  32.448 18.133 32.472 18.995 ;
     RECT  7.8 18.757 8.52 19.333 ;
     RECT  26.112 15.877 26.136 19.333 ;
     RECT  2.4 16.405 3.576 20.579 ;
     RECT  7.8 19.333 9.144 20.579 ;
     RECT  27.504 16.837 27.624 20.579 ;
     RECT  2.4 20.579 3.528 20.915 ;
     RECT  34.8 18.133 35.496 21.109 ;
     RECT  12.432 16.787 13.512 21.155 ;
     RECT  26.112 19.333 26.232 21.155 ;
     RECT  27.888 20.725 27.912 21.443 ;
     RECT  9.984 22.165 10.44 22.645 ;
     RECT  9.984 22.645 10.776 22.693 ;
     RECT  7.8 20.579 8.52 22.741 ;
     RECT  9.696 22.693 10.776 22.741 ;
     RECT  18.24 18.851 18.912 22.835 ;
     RECT  29.4 17.605 30.312 22.835 ;
     RECT  34.8 21.109 35.592 23.075 ;
     RECT  25.584 21.397 25.608 23.411 ;
     RECT  22.224 22.453 22.248 23.555 ;
     RECT  12.48 21.155 13.512 23.557 ;
     RECT  14.64 22.741 14.664 23.557 ;
     RECT  7.8 22.741 10.776 23.605 ;
     RECT  12.48 23.557 14.664 23.605 ;
     RECT  12.48 23.605 15.048 23.653 ;
     RECT  4.8 21.013 4.824 23.797 ;
     RECT  4.8 23.797 5.256 23.843 ;
     RECT  18.6 22.835 18.912 24.085 ;
     RECT  34.8 23.075 35.112 24.229 ;
     RECT  25.296 23.653 25.56 24.323 ;
     RECT  5.232 23.843 5.256 24.469 ;
     RECT  7.8 23.605 10.872 24.469 ;
     RECT  12.48 23.653 15.384 24.469 ;
     RECT  17.04 24.325 17.064 25.093 ;
     RECT  7.8 24.469 15.384 25.139 ;
     RECT  36.48 24.469 36.504 25.139 ;
     RECT  16.944 25.093 17.064 25.141 ;
     RECT  18.6 24.085 19.464 25.187 ;
     RECT  21.408 24.469 21.432 25.187 ;
     RECT  34.656 24.229 35.112 25.235 ;
     RECT  5.232 24.469 5.832 25.331 ;
     RECT  12.48 25.139 15.384 25.331 ;
     RECT  12.48 25.331 14.856 25.715 ;
     RECT  28.224 25.621 28.248 26.197 ;
     RECT  7.8 25.139 8.568 26.243 ;
     RECT  9.6 25.139 11.448 26.243 ;
     RECT  13.104 25.715 14.856 26.243 ;
     RECT  38.208 26.197 38.232 26.245 ;
     RECT  25.536 24.323 25.56 26.531 ;
     RECT  7.8 26.243 8.52 26.533 ;
     RECT  29.4 22.835 29.712 26.629 ;
     RECT  16.848 25.141 17.064 26.771 ;
     RECT  9.6 26.243 11.352 26.819 ;
     RECT  16.848 26.771 16.968 26.819 ;
     RECT  16.848 26.819 16.872 26.867 ;
     RECT  27.456 26.197 28.248 27.155 ;
     RECT  33.024 27.109 33.048 27.205 ;
     RECT  13.104 26.243 14.472 27.395 ;
     RECT  37.44 26.245 38.232 27.395 ;
     RECT  9.84 26.819 11.352 27.781 ;
     RECT  7.68 26.533 8.52 27.829 ;
     RECT  9.84 27.781 11.4 27.829 ;
     RECT  28.224 27.155 28.248 27.875 ;
     RECT  29.4 26.629 29.88 27.877 ;
     RECT  31.008 25.621 31.032 27.877 ;
     RECT  34.8 25.235 35.112 27.877 ;
     RECT  36.432 26.725 36.456 27.877 ;
     RECT  7.68 27.829 11.4 27.971 ;
     RECT  13.2 27.395 14.472 28.357 ;
     RECT  33.024 27.205 33.096 28.405 ;
     RECT  7.8 27.971 11.4 28.453 ;
     RECT  18.6 25.187 18.912 28.453 ;
     RECT  32.448 28.405 33.096 28.547 ;
     RECT  20.544 27.301 20.568 28.691 ;
     RECT  5.232 25.331 5.256 29.123 ;
     RECT  13.104 28.357 14.472 29.123 ;
     RECT  29.4 27.877 31.032 29.123 ;
     RECT  32.448 28.547 32.472 29.123 ;
     RECT  37.44 27.395 37.464 29.219 ;
     RECT  18.6 28.453 19.272 29.267 ;
     RECT  22.8 29.269 22.824 29.459 ;
     RECT  34.8 27.877 36.456 29.603 ;
     RECT  29.4 29.123 29.88 29.699 ;
     RECT  26.112 28.789 26.136 29.747 ;
     RECT  31.008 29.123 31.032 29.987 ;
     RECT  7.8 28.453 11.976 30.037 ;
     RECT  2.4 20.915 3.432 30.181 ;
     RECT  16.32 29.365 16.344 30.275 ;
     RECT  18.6 29.267 18.912 30.325 ;
     RECT  7.632 30.037 11.976 30.421 ;
     RECT  27.552 29.509 27.576 30.563 ;
     RECT  6.96 30.421 11.976 30.707 ;
     RECT  2.4 30.181 3.816 30.709 ;
     RECT  9.168 30.707 11.976 30.803 ;
     RECT  13.2 29.123 14.472 30.805 ;
     RECT  2.4 30.709 4.68 30.851 ;
     RECT  13.104 30.805 14.472 30.947 ;
     RECT  6.96 30.707 8.112 31.141 ;
     RECT  3.792 30.851 4.68 31.235 ;
     RECT  13.104 30.947 14.088 31.427 ;
     RECT  36.432 29.603 36.456 31.619 ;
     RECT  18.6 30.325 19.272 31.667 ;
     RECT  4.56 31.235 4.584 31.715 ;
     RECT  6.864 31.141 8.112 32.003 ;
     RECT  13.2 31.427 14.088 32.051 ;
     RECT  7.8 32.003 8.112 32.053 ;
     RECT  9.168 30.803 11.256 32.053 ;
     RECT  2.4 30.851 2.712 32.409 ;
     RECT  7.8 32.053 11.256 32.409 ;
     RECT  13.2 32.051 13.512 32.409 ;
     RECT  18.6 31.667 18.912 32.409 ;
     RECT  24 7.091 24.312 32.409 ;
     RECT  29.4 29.699 29.712 32.409 ;
     RECT  34.8 29.603 35.112 32.409 ;
     RECT  40.2 16.019 40.512 32.409 ;
     RECT  2.4 32.409 2.52 32.423 ;
     RECT  7.8 32.409 7.92 32.423 ;
     RECT  13.2 32.409 13.32 32.423 ;
     RECT  18.6 32.409 18.72 32.423 ;
     RECT  24 32.409 24.12 32.423 ;
     RECT  29.4 32.409 29.52 32.423 ;
     RECT  34.8 32.409 34.92 32.423 ;
     RECT  40.2 32.409 40.32 32.423 ;
     RECT  9.024 32.409 11.256 33.061 ;
     RECT  9.024 33.061 11.352 34.384 ;
     RECT  9.6 1.763 9.648 2.151 ;
     RECT  8.112 2.151 9.648 2.869 ;
     RECT  2.856 2.773 3.936 4.115 ;
     RECT  17.16 2.821 18.6 3.397 ;
     RECT  8.112 2.869 9.456 3.541 ;
     RECT  17.16 3.397 18.48 3.443 ;
     RECT  6.024 3.637 7.488 4.405 ;
     RECT  2.712 4.115 3.936 5.747 ;
     RECT  6.024 4.405 7.44 5.171 ;
     RECT  37.512 5.029 38.736 5.989 ;
     RECT  38.76 5.029 40.2 6.035 ;
     RECT  27.96 5.077 29.4 12.035 ;
     RECT  14.184 8.003 14.232 9.061 ;
     RECT  16.392 8.485 17.568 9.107 ;
     RECT  17.592 8.485 18.6 15.445 ;
     RECT  18.912 8.821 20.112 9.539 ;
     RECT  25.992 8.965 27.024 9.251 ;
     RECT  14.184 9.061 15.36 11.653 ;
     RECT  15.384 9.061 16.368 9.107 ;
     RECT  10.008 9.491 11.088 10.355 ;
     RECT  38.328 10.165 39.792 10.211 ;
     RECT  10.008 10.355 11.184 10.883 ;
     RECT  10.008 10.883 11.376 11.699 ;
     RECT  8.328 10.979 9.6 12.563 ;
     RECT  7.68 11.459 7.8 12.517 ;
     RECT  14.28 11.653 15.36 12.373 ;
     RECT  29.28 12.035 29.4 12.997 ;
     RECT  8.112 12.563 9.6 15.491 ;
     RECT  15.144 12.755 15.384 13.139 ;
     RECT  21 12.901 22.224 13.429 ;
     RECT  14.28 13.139 15.384 13.427 ;
     RECT  13.512 13.427 15.384 13.957 ;
     RECT  21.096 13.429 22.224 14.867 ;
     RECT  13.512 13.957 16.32 14.485 ;
     RECT  16.344 13.957 17.568 14.773 ;
     RECT  13.512 14.485 14.784 16.019 ;
     RECT  14.808 14.485 16.32 14.867 ;
     RECT  16.344 14.773 17.328 14.867 ;
     RECT  12.12 14.915 13.2 16.741 ;
     RECT  28.152 15.685 29.28 16.259 ;
     RECT  26.136 15.877 27.6 16.837 ;
     RECT  26.136 16.837 27.504 19.333 ;
     RECT  15.96 17.173 17.328 18.275 ;
     RECT  38.904 18.613 40.2 18.803 ;
     RECT  26.232 19.333 27.504 20.579 ;
     RECT  3.528 20.579 3.576 20.915 ;
     RECT  27.912 20.725 29.4 21.443 ;
     RECT  3.432 20.915 3.576 21.013 ;
     RECT  3.432 21.013 4.8 23.843 ;
     RECT  24.312 21.397 25.584 23.411 ;
     RECT  8.52 22.165 9.984 22.693 ;
     RECT  8.52 22.693 9.696 22.741 ;
     RECT  13.512 22.741 14.64 23.557 ;
     RECT  35.112 23.075 35.592 24.469 ;
     RECT  24.312 23.411 25.56 23.653 ;
     RECT  24.312 23.653 25.296 24.323 ;
     RECT  24.312 24.323 25.536 26.531 ;
     RECT  35.112 24.469 36.48 25.139 ;
     RECT  8.568 25.139 9.6 26.243 ;
     RECT  11.448 25.139 12.48 25.715 ;
     RECT  15.384 25.141 16.848 25.331 ;
     RECT  28.248 25.621 29.4 27.875 ;
     RECT  29.712 25.621 31.008 26.629 ;
     RECT  8.52 26.243 9.6 26.819 ;
     RECT  29.88 26.629 31.008 27.877 ;
     RECT  35.112 26.725 36.432 27.877 ;
     RECT  36.456 26.725 37.44 29.219 ;
     RECT  8.52 26.819 9.84 27.829 ;
     RECT  13.104 27.395 13.2 28.357 ;
     RECT  31.032 28.405 32.448 29.123 ;
     RECT  11.976 28.453 13.104 29.123 ;
     RECT  19.272 28.453 20.544 28.691 ;
     RECT  11.976 29.123 13.2 30.803 ;
     RECT  29.88 29.123 31.008 29.699 ;
     RECT  18.912 29.267 19.272 30.325 ;
     RECT  22.824 29.269 24 29.459 ;
     RECT  26.136 29.509 27.552 29.747 ;
     RECT  35.112 29.603 36.432 31.619 ;
     RECT  29.712 29.699 31.008 29.987 ;
     RECT  8.112 30.707 9.168 32.053 ;
     RECT  13.104 30.803 13.2 30.805 ;
     RECT  2.712 30.851 3.792 31.235 ;
     RECT  7.92 32.409 9.024 32.423 ;
  END
END ot_s81_markov_join_native
END LIBRARY
